VERSION 5.8 ;
BUSBITCHARS "[]" ;
DIVIDERCHAR "/" ;
UNITS
    DATABASE MICRONS 1000 ;
END UNITS

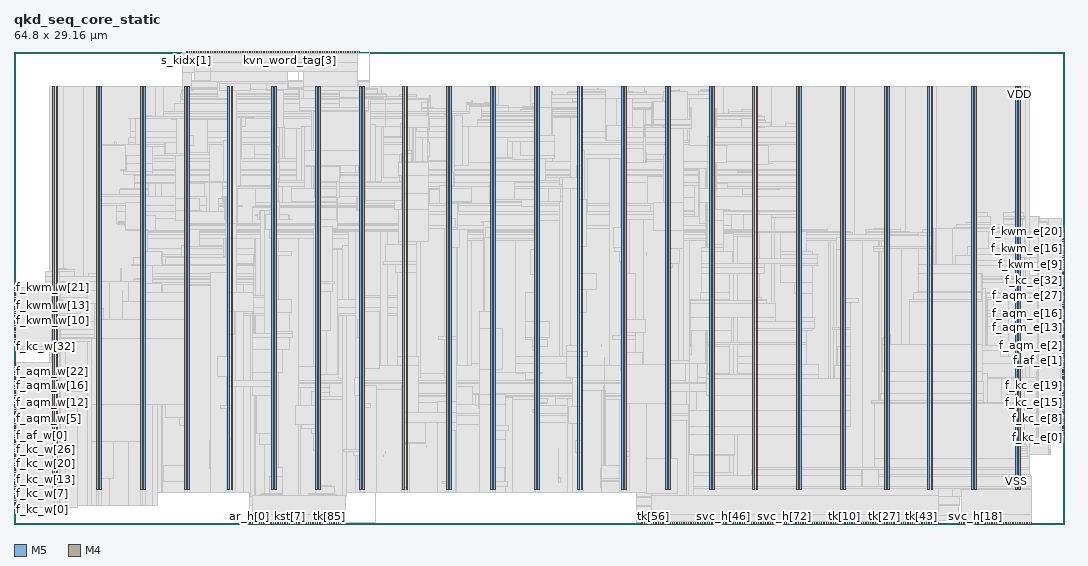
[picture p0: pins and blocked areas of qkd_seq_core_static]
MACRO qkd_seq_core_static
  FOREIGN qkd_seq_core_static 0 0 ;
  CLASS BLOCK ;
  SIZE 64.8 BY 29.16 ;
  PIN ar_h[0]
    DIRECTION INPUT ;
    USE SIGNAL ;
    PORT
      LAYER M5 ;
        RECT  14.544 0 14.568 0.084 ;
    END
  END ar_h[0]
  PIN ar_h[1]
    DIRECTION INPUT ;
    USE SIGNAL ;
    PORT
      LAYER M5 ;
        RECT  14.688 0 14.712 0.084 ;
    END
  END ar_h[1]
  PIN ar_h[2]
    DIRECTION INPUT ;
    USE SIGNAL ;
    PORT
      LAYER M5 ;
        RECT  14.832 0 14.856 0.084 ;
    END
  END ar_h[2]
  PIN ar_h[3]
    DIRECTION INPUT ;
    USE SIGNAL ;
    PORT
      LAYER M5 ;
        RECT  14.976 0 15 0.084 ;
    END
  END ar_h[3]
  PIN ar_h[4]
    DIRECTION INPUT ;
    USE SIGNAL ;
    PORT
      LAYER M5 ;
        RECT  15.12 0 15.144 0.084 ;
    END
  END ar_h[4]
  PIN ar_h[5]
    DIRECTION INPUT ;
    USE SIGNAL ;
    PORT
      LAYER M5 ;
        RECT  15.264 0 15.288 0.084 ;
    END
  END ar_h[5]
  PIN ar_h[6]
    DIRECTION INPUT ;
    USE SIGNAL ;
    PORT
      LAYER M5 ;
        RECT  15.408 0 15.432 0.084 ;
    END
  END ar_h[6]
  PIN ar_h[7]
    DIRECTION INPUT ;
    USE SIGNAL ;
    PORT
      LAYER M5 ;
        RECT  15.552 0 15.576 0.084 ;
    END
  END ar_h[7]
  PIN att_rx_beat[0]
    DIRECTION INPUT ;
    USE SIGNAL ;
    PORT
      LAYER M5 ;
        RECT  12.24 29.076 12.264 29.16 ;
    END
  END att_rx_beat[0]
  PIN att_rx_beat[1]
    DIRECTION INPUT ;
    USE SIGNAL ;
    PORT
      LAYER M5 ;
        RECT  12.384 29.076 12.408 29.16 ;
    END
  END att_rx_beat[1]
  PIN att_rx_beat[2]
    DIRECTION INPUT ;
    USE SIGNAL ;
    PORT
      LAYER M5 ;
        RECT  12.528 29.076 12.552 29.16 ;
    END
  END att_rx_beat[2]
  PIN att_rx_beat[3]
    DIRECTION INPUT ;
    USE SIGNAL ;
    PORT
      LAYER M5 ;
        RECT  12.672 29.076 12.696 29.16 ;
    END
  END att_rx_beat[3]
  PIN att_rx_beat[4]
    DIRECTION INPUT ;
    USE SIGNAL ;
    PORT
      LAYER M5 ;
        RECT  12.816 29.076 12.84 29.16 ;
    END
  END att_rx_beat[4]
  PIN att_rx_kind[0]
    DIRECTION INPUT ;
    USE SIGNAL ;
    PORT
      LAYER M5 ;
        RECT  12.96 29.076 12.984 29.16 ;
    END
  END att_rx_kind[0]
  PIN att_rx_kind[1]
    DIRECTION INPUT ;
    USE SIGNAL ;
    PORT
      LAYER M5 ;
        RECT  13.104 29.076 13.128 29.16 ;
    END
  END att_rx_kind[1]
  PIN att_rx_kind[2]
    DIRECTION INPUT ;
    USE SIGNAL ;
    PORT
      LAYER M5 ;
        RECT  13.248 29.076 13.272 29.16 ;
    END
  END att_rx_kind[2]
  PIN att_rx_kind[3]
    DIRECTION INPUT ;
    USE SIGNAL ;
    PORT
      LAYER M5 ;
        RECT  13.392 29.076 13.416 29.16 ;
    END
  END att_rx_kind[3]
  PIN att_rx_v
    DIRECTION INPUT ;
    USE SIGNAL ;
    PORT
      LAYER M5 ;
        RECT  13.536 29.076 13.56 29.16 ;
    END
  END att_rx_v
  PIN ck
    DIRECTION INPUT ;
    USE SIGNAL ;
    PORT
      LAYER M5 ;
        RECT  13.68 29.076 13.704 29.16 ;
    END
  END ck
  PIN cmd_d[0]
    DIRECTION INPUT ;
    USE SIGNAL ;
    PORT
      LAYER M5 ;
        RECT  13.824 29.076 13.848 29.16 ;
    END
  END cmd_d[0]
  PIN cmd_d[10]
    DIRECTION INPUT ;
    USE SIGNAL ;
    PORT
      LAYER M5 ;
        RECT  15.264 29.076 15.288 29.16 ;
    END
  END cmd_d[10]
  PIN cmd_d[11]
    DIRECTION INPUT ;
    USE SIGNAL ;
    PORT
      LAYER M5 ;
        RECT  15.408 29.076 15.432 29.16 ;
    END
  END cmd_d[11]
  PIN cmd_d[12]
    DIRECTION INPUT ;
    USE SIGNAL ;
    PORT
      LAYER M5 ;
        RECT  15.552 29.076 15.576 29.16 ;
    END
  END cmd_d[12]
  PIN cmd_d[13]
    DIRECTION INPUT ;
    USE SIGNAL ;
    PORT
      LAYER M5 ;
        RECT  15.696 29.076 15.72 29.16 ;
    END
  END cmd_d[13]
  PIN cmd_d[14]
    DIRECTION INPUT ;
    USE SIGNAL ;
    PORT
      LAYER M5 ;
        RECT  15.84 29.076 15.864 29.16 ;
    END
  END cmd_d[14]
  PIN cmd_d[15]
    DIRECTION INPUT ;
    USE SIGNAL ;
    PORT
      LAYER M5 ;
        RECT  15.984 29.076 16.008 29.16 ;
    END
  END cmd_d[15]
  PIN cmd_d[16]
    DIRECTION INPUT ;
    USE SIGNAL ;
    PORT
      LAYER M5 ;
        RECT  16.128 29.076 16.152 29.16 ;
    END
  END cmd_d[16]
  PIN cmd_d[17]
    DIRECTION INPUT ;
    USE SIGNAL ;
    PORT
      LAYER M5 ;
        RECT  16.272 29.076 16.296 29.16 ;
    END
  END cmd_d[17]
  PIN cmd_d[18]
    DIRECTION INPUT ;
    USE SIGNAL ;
    PORT
      LAYER M5 ;
        RECT  16.416 29.076 16.44 29.16 ;
    END
  END cmd_d[18]
  PIN cmd_d[1]
    DIRECTION INPUT ;
    USE SIGNAL ;
    PORT
      LAYER M5 ;
        RECT  13.968 29.076 13.992 29.16 ;
    END
  END cmd_d[1]
  PIN cmd_d[2]
    DIRECTION INPUT ;
    USE SIGNAL ;
    PORT
      LAYER M5 ;
        RECT  14.112 29.076 14.136 29.16 ;
    END
  END cmd_d[2]
  PIN cmd_d[3]
    DIRECTION INPUT ;
    USE SIGNAL ;
    PORT
      LAYER M5 ;
        RECT  14.256 29.076 14.28 29.16 ;
    END
  END cmd_d[3]
  PIN cmd_d[4]
    DIRECTION INPUT ;
    USE SIGNAL ;
    PORT
      LAYER M5 ;
        RECT  14.4 29.076 14.424 29.16 ;
    END
  END cmd_d[4]
  PIN cmd_d[5]
    DIRECTION INPUT ;
    USE SIGNAL ;
    PORT
      LAYER M5 ;
        RECT  14.544 29.076 14.568 29.16 ;
    END
  END cmd_d[5]
  PIN cmd_d[6]
    DIRECTION INPUT ;
    USE SIGNAL ;
    PORT
      LAYER M5 ;
        RECT  14.688 29.076 14.712 29.16 ;
    END
  END cmd_d[6]
  PIN cmd_d[7]
    DIRECTION INPUT ;
    USE SIGNAL ;
    PORT
      LAYER M5 ;
        RECT  14.832 29.076 14.856 29.16 ;
    END
  END cmd_d[7]
  PIN cmd_d[8]
    DIRECTION INPUT ;
    USE SIGNAL ;
    PORT
      LAYER M5 ;
        RECT  14.976 29.076 15 29.16 ;
    END
  END cmd_d[8]
  PIN cmd_d[9]
    DIRECTION INPUT ;
    USE SIGNAL ;
    PORT
      LAYER M5 ;
        RECT  15.12 29.076 15.144 29.16 ;
    END
  END cmd_d[9]
  PIN f_af_e[0]
    DIRECTION INPUT ;
    USE SIGNAL ;
    PORT
      LAYER M4 ;
        RECT  64.716 9.936 64.8 9.96 ;
    END
  END f_af_e[0]
  PIN f_af_e[1]
    DIRECTION INPUT ;
    USE SIGNAL ;
    PORT
      LAYER M4 ;
        RECT  64.716 10.08 64.8 10.104 ;
    END
  END f_af_e[1]
  PIN f_af_w[0]
    DIRECTION INPUT ;
    USE SIGNAL ;
    PORT
      LAYER M4 ;
        RECT  0 5.472 0.084 5.496 ;
    END
  END f_af_w[0]
  PIN f_af_w[1]
    DIRECTION INPUT ;
    USE SIGNAL ;
    PORT
      LAYER M4 ;
        RECT  0 5.616 0.084 5.64 ;
    END
  END f_af_w[1]
  PIN f_aqm_e[0]
    DIRECTION OUTPUT ;
    USE SIGNAL ;
    PORT
      LAYER M4 ;
        RECT  64.716 10.224 64.8 10.248 ;
    END
  END f_aqm_e[0]
  PIN f_aqm_e[10]
    DIRECTION OUTPUT ;
    USE SIGNAL ;
    PORT
      LAYER M4 ;
        RECT  64.716 11.664 64.8 11.688 ;
    END
  END f_aqm_e[10]
  PIN f_aqm_e[11]
    DIRECTION OUTPUT ;
    USE SIGNAL ;
    PORT
      LAYER M4 ;
        RECT  64.716 11.808 64.8 11.832 ;
    END
  END f_aqm_e[11]
  PIN f_aqm_e[12]
    DIRECTION OUTPUT ;
    USE SIGNAL ;
    PORT
      LAYER M4 ;
        RECT  64.716 11.952 64.8 11.976 ;
    END
  END f_aqm_e[12]
  PIN f_aqm_e[13]
    DIRECTION OUTPUT ;
    USE SIGNAL ;
    PORT
      LAYER M4 ;
        RECT  64.716 12.096 64.8 12.12 ;
    END
  END f_aqm_e[13]
  PIN f_aqm_e[14]
    DIRECTION OUTPUT ;
    USE SIGNAL ;
    PORT
      LAYER M4 ;
        RECT  64.716 12.24 64.8 12.264 ;
    END
  END f_aqm_e[14]
  PIN f_aqm_e[15]
    DIRECTION OUTPUT ;
    USE SIGNAL ;
    PORT
      LAYER M4 ;
        RECT  64.716 12.384 64.8 12.408 ;
    END
  END f_aqm_e[15]
  PIN f_aqm_e[16]
    DIRECTION OUTPUT ;
    USE SIGNAL ;
    PORT
      LAYER M4 ;
        RECT  64.716 12.528 64.8 12.552 ;
    END
  END f_aqm_e[16]
  PIN f_aqm_e[17]
    DIRECTION OUTPUT ;
    USE SIGNAL ;
    PORT
      LAYER M4 ;
        RECT  64.716 12.672 64.8 12.696 ;
    END
  END f_aqm_e[17]
  PIN f_aqm_e[18]
    DIRECTION OUTPUT ;
    USE SIGNAL ;
    PORT
      LAYER M4 ;
        RECT  64.716 12.816 64.8 12.84 ;
    END
  END f_aqm_e[18]
  PIN f_aqm_e[19]
    DIRECTION OUTPUT ;
    USE SIGNAL ;
    PORT
      LAYER M4 ;
        RECT  64.716 12.96 64.8 12.984 ;
    END
  END f_aqm_e[19]
  PIN f_aqm_e[1]
    DIRECTION OUTPUT ;
    USE SIGNAL ;
    PORT
      LAYER M4 ;
        RECT  64.716 10.368 64.8 10.392 ;
    END
  END f_aqm_e[1]
  PIN f_aqm_e[20]
    DIRECTION OUTPUT ;
    USE SIGNAL ;
    PORT
      LAYER M4 ;
        RECT  64.716 13.104 64.8 13.128 ;
    END
  END f_aqm_e[20]
  PIN f_aqm_e[21]
    DIRECTION OUTPUT ;
    USE SIGNAL ;
    PORT
      LAYER M4 ;
        RECT  64.716 13.248 64.8 13.272 ;
    END
  END f_aqm_e[21]
  PIN f_aqm_e[22]
    DIRECTION OUTPUT ;
    USE SIGNAL ;
    PORT
      LAYER M4 ;
        RECT  64.716 13.392 64.8 13.416 ;
    END
  END f_aqm_e[22]
  PIN f_aqm_e[23]
    DIRECTION OUTPUT ;
    USE SIGNAL ;
    PORT
      LAYER M4 ;
        RECT  64.716 13.536 64.8 13.56 ;
    END
  END f_aqm_e[23]
  PIN f_aqm_e[24]
    DIRECTION OUTPUT ;
    USE SIGNAL ;
    PORT
      LAYER M4 ;
        RECT  64.716 13.68 64.8 13.704 ;
    END
  END f_aqm_e[24]
  PIN f_aqm_e[25]
    DIRECTION OUTPUT ;
    USE SIGNAL ;
    PORT
      LAYER M4 ;
        RECT  64.716 13.824 64.8 13.848 ;
    END
  END f_aqm_e[25]
  PIN f_aqm_e[26]
    DIRECTION OUTPUT ;
    USE SIGNAL ;
    PORT
      LAYER M4 ;
        RECT  64.716 13.968 64.8 13.992 ;
    END
  END f_aqm_e[26]
  PIN f_aqm_e[27]
    DIRECTION OUTPUT ;
    USE SIGNAL ;
    PORT
      LAYER M4 ;
        RECT  64.716 14.112 64.8 14.136 ;
    END
  END f_aqm_e[27]
  PIN f_aqm_e[2]
    DIRECTION OUTPUT ;
    USE SIGNAL ;
    PORT
      LAYER M4 ;
        RECT  64.716 10.512 64.8 10.536 ;
    END
  END f_aqm_e[2]
  PIN f_aqm_e[3]
    DIRECTION OUTPUT ;
    USE SIGNAL ;
    PORT
      LAYER M4 ;
        RECT  64.716 10.656 64.8 10.68 ;
    END
  END f_aqm_e[3]
  PIN f_aqm_e[4]
    DIRECTION OUTPUT ;
    USE SIGNAL ;
    PORT
      LAYER M4 ;
        RECT  64.716 10.8 64.8 10.824 ;
    END
  END f_aqm_e[4]
  PIN f_aqm_e[5]
    DIRECTION OUTPUT ;
    USE SIGNAL ;
    PORT
      LAYER M4 ;
        RECT  64.716 10.944 64.8 10.968 ;
    END
  END f_aqm_e[5]
  PIN f_aqm_e[6]
    DIRECTION OUTPUT ;
    USE SIGNAL ;
    PORT
      LAYER M4 ;
        RECT  64.716 11.088 64.8 11.112 ;
    END
  END f_aqm_e[6]
  PIN f_aqm_e[7]
    DIRECTION OUTPUT ;
    USE SIGNAL ;
    PORT
      LAYER M4 ;
        RECT  64.716 11.232 64.8 11.256 ;
    END
  END f_aqm_e[7]
  PIN f_aqm_e[8]
    DIRECTION OUTPUT ;
    USE SIGNAL ;
    PORT
      LAYER M4 ;
        RECT  64.716 11.376 64.8 11.4 ;
    END
  END f_aqm_e[8]
  PIN f_aqm_e[9]
    DIRECTION OUTPUT ;
    USE SIGNAL ;
    PORT
      LAYER M4 ;
        RECT  64.716 11.52 64.8 11.544 ;
    END
  END f_aqm_e[9]
  PIN f_aqm_w[0]
    DIRECTION OUTPUT ;
    USE SIGNAL ;
    PORT
      LAYER M4 ;
        RECT  0 5.76 0.084 5.784 ;
    END
  END f_aqm_w[0]
  PIN f_aqm_w[10]
    DIRECTION OUTPUT ;
    USE SIGNAL ;
    PORT
      LAYER M4 ;
        RECT  0 7.2 0.084 7.224 ;
    END
  END f_aqm_w[10]
  PIN f_aqm_w[11]
    DIRECTION OUTPUT ;
    USE SIGNAL ;
    PORT
      LAYER M4 ;
        RECT  0 7.344 0.084 7.368 ;
    END
  END f_aqm_w[11]
  PIN f_aqm_w[12]
    DIRECTION OUTPUT ;
    USE SIGNAL ;
    PORT
      LAYER M4 ;
        RECT  0 7.488 0.084 7.512 ;
    END
  END f_aqm_w[12]
  PIN f_aqm_w[13]
    DIRECTION OUTPUT ;
    USE SIGNAL ;
    PORT
      LAYER M4 ;
        RECT  0 7.632 0.084 7.656 ;
    END
  END f_aqm_w[13]
  PIN f_aqm_w[14]
    DIRECTION OUTPUT ;
    USE SIGNAL ;
    PORT
      LAYER M4 ;
        RECT  0 7.776 0.084 7.8 ;
    END
  END f_aqm_w[14]
  PIN f_aqm_w[15]
    DIRECTION OUTPUT ;
    USE SIGNAL ;
    PORT
      LAYER M4 ;
        RECT  0 7.92 0.084 7.944 ;
    END
  END f_aqm_w[15]
  PIN f_aqm_w[16]
    DIRECTION OUTPUT ;
    USE SIGNAL ;
    PORT
      LAYER M4 ;
        RECT  0 8.064 0.084 8.088 ;
    END
  END f_aqm_w[16]
  PIN f_aqm_w[17]
    DIRECTION OUTPUT ;
    USE SIGNAL ;
    PORT
      LAYER M4 ;
        RECT  0 8.208 0.084 8.232 ;
    END
  END f_aqm_w[17]
  PIN f_aqm_w[18]
    DIRECTION OUTPUT ;
    USE SIGNAL ;
    PORT
      LAYER M4 ;
        RECT  0 8.352 0.084 8.376 ;
    END
  END f_aqm_w[18]
  PIN f_aqm_w[19]
    DIRECTION OUTPUT ;
    USE SIGNAL ;
    PORT
      LAYER M4 ;
        RECT  0 8.496 0.084 8.52 ;
    END
  END f_aqm_w[19]
  PIN f_aqm_w[1]
    DIRECTION OUTPUT ;
    USE SIGNAL ;
    PORT
      LAYER M4 ;
        RECT  0 5.904 0.084 5.928 ;
    END
  END f_aqm_w[1]
  PIN f_aqm_w[20]
    DIRECTION OUTPUT ;
    USE SIGNAL ;
    PORT
      LAYER M4 ;
        RECT  0 8.64 0.084 8.664 ;
    END
  END f_aqm_w[20]
  PIN f_aqm_w[21]
    DIRECTION OUTPUT ;
    USE SIGNAL ;
    PORT
      LAYER M4 ;
        RECT  0 8.784 0.084 8.808 ;
    END
  END f_aqm_w[21]
  PIN f_aqm_w[22]
    DIRECTION OUTPUT ;
    USE SIGNAL ;
    PORT
      LAYER M4 ;
        RECT  0 8.928 0.084 8.952 ;
    END
  END f_aqm_w[22]
  PIN f_aqm_w[23]
    DIRECTION OUTPUT ;
    USE SIGNAL ;
    PORT
      LAYER M4 ;
        RECT  0 9.072 0.084 9.096 ;
    END
  END f_aqm_w[23]
  PIN f_aqm_w[24]
    DIRECTION OUTPUT ;
    USE SIGNAL ;
    PORT
      LAYER M4 ;
        RECT  0 9.216 0.084 9.24 ;
    END
  END f_aqm_w[24]
  PIN f_aqm_w[25]
    DIRECTION OUTPUT ;
    USE SIGNAL ;
    PORT
      LAYER M4 ;
        RECT  0 9.36 0.084 9.384 ;
    END
  END f_aqm_w[25]
  PIN f_aqm_w[26]
    DIRECTION OUTPUT ;
    USE SIGNAL ;
    PORT
      LAYER M4 ;
        RECT  0 9.504 0.084 9.528 ;
    END
  END f_aqm_w[26]
  PIN f_aqm_w[27]
    DIRECTION OUTPUT ;
    USE SIGNAL ;
    PORT
      LAYER M4 ;
        RECT  0 9.648 0.084 9.672 ;
    END
  END f_aqm_w[27]
  PIN f_aqm_w[2]
    DIRECTION OUTPUT ;
    USE SIGNAL ;
    PORT
      LAYER M4 ;
        RECT  0 6.048 0.084 6.072 ;
    END
  END f_aqm_w[2]
  PIN f_aqm_w[3]
    DIRECTION OUTPUT ;
    USE SIGNAL ;
    PORT
      LAYER M4 ;
        RECT  0 6.192 0.084 6.216 ;
    END
  END f_aqm_w[3]
  PIN f_aqm_w[4]
    DIRECTION OUTPUT ;
    USE SIGNAL ;
    PORT
      LAYER M4 ;
        RECT  0 6.336 0.084 6.36 ;
    END
  END f_aqm_w[4]
  PIN f_aqm_w[5]
    DIRECTION OUTPUT ;
    USE SIGNAL ;
    PORT
      LAYER M4 ;
        RECT  0 6.48 0.084 6.504 ;
    END
  END f_aqm_w[5]
  PIN f_aqm_w[6]
    DIRECTION OUTPUT ;
    USE SIGNAL ;
    PORT
      LAYER M4 ;
        RECT  0 6.624 0.084 6.648 ;
    END
  END f_aqm_w[6]
  PIN f_aqm_w[7]
    DIRECTION OUTPUT ;
    USE SIGNAL ;
    PORT
      LAYER M4 ;
        RECT  0 6.768 0.084 6.792 ;
    END
  END f_aqm_w[7]
  PIN f_aqm_w[8]
    DIRECTION OUTPUT ;
    USE SIGNAL ;
    PORT
      LAYER M4 ;
        RECT  0 6.912 0.084 6.936 ;
    END
  END f_aqm_w[8]
  PIN f_aqm_w[9]
    DIRECTION OUTPUT ;
    USE SIGNAL ;
    PORT
      LAYER M4 ;
        RECT  0 7.056 0.084 7.08 ;
    END
  END f_aqm_w[9]
  PIN f_cr_e[0]
    DIRECTION INPUT ;
    USE SIGNAL ;
    PORT
      LAYER M4 ;
        RECT  64.716 14.256 64.8 14.28 ;
    END
  END f_cr_e[0]
  PIN f_cr_e[1]
    DIRECTION INPUT ;
    USE SIGNAL ;
    PORT
      LAYER M4 ;
        RECT  64.716 14.4 64.8 14.424 ;
    END
  END f_cr_e[1]
  PIN f_cr_w[0]
    DIRECTION INPUT ;
    USE SIGNAL ;
    PORT
      LAYER M4 ;
        RECT  0 9.792 0.084 9.816 ;
    END
  END f_cr_w[0]
  PIN f_cr_w[1]
    DIRECTION INPUT ;
    USE SIGNAL ;
    PORT
      LAYER M4 ;
        RECT  0 9.936 0.084 9.96 ;
    END
  END f_cr_w[1]
  PIN f_kc_e[0]
    DIRECTION OUTPUT ;
    USE SIGNAL ;
    PORT
      LAYER M4 ;
        RECT  64.716 5.328 64.8 5.352 ;
    END
  END f_kc_e[0]
  PIN f_kc_e[10]
    DIRECTION OUTPUT ;
    USE SIGNAL ;
    PORT
      LAYER M4 ;
        RECT  64.716 6.768 64.8 6.792 ;
    END
  END f_kc_e[10]
  PIN f_kc_e[11]
    DIRECTION OUTPUT ;
    USE SIGNAL ;
    PORT
      LAYER M4 ;
        RECT  64.716 6.912 64.8 6.936 ;
    END
  END f_kc_e[11]
  PIN f_kc_e[12]
    DIRECTION OUTPUT ;
    USE SIGNAL ;
    PORT
      LAYER M4 ;
        RECT  64.716 7.056 64.8 7.08 ;
    END
  END f_kc_e[12]
  PIN f_kc_e[13]
    DIRECTION OUTPUT ;
    USE SIGNAL ;
    PORT
      LAYER M4 ;
        RECT  64.716 7.2 64.8 7.224 ;
    END
  END f_kc_e[13]
  PIN f_kc_e[14]
    DIRECTION OUTPUT ;
    USE SIGNAL ;
    PORT
      LAYER M4 ;
        RECT  64.716 7.344 64.8 7.368 ;
    END
  END f_kc_e[14]
  PIN f_kc_e[15]
    DIRECTION OUTPUT ;
    USE SIGNAL ;
    PORT
      LAYER M4 ;
        RECT  64.716 7.488 64.8 7.512 ;
    END
  END f_kc_e[15]
  PIN f_kc_e[16]
    DIRECTION OUTPUT ;
    USE SIGNAL ;
    PORT
      LAYER M4 ;
        RECT  64.716 7.632 64.8 7.656 ;
    END
  END f_kc_e[16]
  PIN f_kc_e[17]
    DIRECTION OUTPUT ;
    USE SIGNAL ;
    PORT
      LAYER M4 ;
        RECT  64.716 7.776 64.8 7.8 ;
    END
  END f_kc_e[17]
  PIN f_kc_e[18]
    DIRECTION OUTPUT ;
    USE SIGNAL ;
    PORT
      LAYER M4 ;
        RECT  64.716 7.92 64.8 7.944 ;
    END
  END f_kc_e[18]
  PIN f_kc_e[19]
    DIRECTION OUTPUT ;
    USE SIGNAL ;
    PORT
      LAYER M4 ;
        RECT  64.716 8.064 64.8 8.088 ;
    END
  END f_kc_e[19]
  PIN f_kc_e[1]
    DIRECTION OUTPUT ;
    USE SIGNAL ;
    PORT
      LAYER M4 ;
        RECT  64.716 5.472 64.8 5.496 ;
    END
  END f_kc_e[1]
  PIN f_kc_e[20]
    DIRECTION OUTPUT ;
    USE SIGNAL ;
    PORT
      LAYER M4 ;
        RECT  64.716 8.208 64.8 8.232 ;
    END
  END f_kc_e[20]
  PIN f_kc_e[21]
    DIRECTION OUTPUT ;
    USE SIGNAL ;
    PORT
      LAYER M4 ;
        RECT  64.716 8.352 64.8 8.376 ;
    END
  END f_kc_e[21]
  PIN f_kc_e[22]
    DIRECTION OUTPUT ;
    USE SIGNAL ;
    PORT
      LAYER M4 ;
        RECT  64.716 8.496 64.8 8.52 ;
    END
  END f_kc_e[22]
  PIN f_kc_e[23]
    DIRECTION OUTPUT ;
    USE SIGNAL ;
    PORT
      LAYER M4 ;
        RECT  64.716 8.64 64.8 8.664 ;
    END
  END f_kc_e[23]
  PIN f_kc_e[24]
    DIRECTION OUTPUT ;
    USE SIGNAL ;
    PORT
      LAYER M4 ;
        RECT  64.716 8.784 64.8 8.808 ;
    END
  END f_kc_e[24]
  PIN f_kc_e[25]
    DIRECTION OUTPUT ;
    USE SIGNAL ;
    PORT
      LAYER M4 ;
        RECT  64.716 8.928 64.8 8.952 ;
    END
  END f_kc_e[25]
  PIN f_kc_e[26]
    DIRECTION OUTPUT ;
    USE SIGNAL ;
    PORT
      LAYER M4 ;
        RECT  64.716 9.072 64.8 9.096 ;
    END
  END f_kc_e[26]
  PIN f_kc_e[27]
    DIRECTION OUTPUT ;
    USE SIGNAL ;
    PORT
      LAYER M4 ;
        RECT  64.716 9.216 64.8 9.24 ;
    END
  END f_kc_e[27]
  PIN f_kc_e[28]
    DIRECTION OUTPUT ;
    USE SIGNAL ;
    PORT
      LAYER M4 ;
        RECT  64.716 9.36 64.8 9.384 ;
    END
  END f_kc_e[28]
  PIN f_kc_e[29]
    DIRECTION OUTPUT ;
    USE SIGNAL ;
    PORT
      LAYER M4 ;
        RECT  64.716 9.504 64.8 9.528 ;
    END
  END f_kc_e[29]
  PIN f_kc_e[2]
    DIRECTION OUTPUT ;
    USE SIGNAL ;
    PORT
      LAYER M4 ;
        RECT  64.716 5.616 64.8 5.64 ;
    END
  END f_kc_e[2]
  PIN f_kc_e[30]
    DIRECTION OUTPUT ;
    USE SIGNAL ;
    PORT
      LAYER M4 ;
        RECT  64.716 9.648 64.8 9.672 ;
    END
  END f_kc_e[30]
  PIN f_kc_e[31]
    DIRECTION OUTPUT ;
    USE SIGNAL ;
    PORT
      LAYER M4 ;
        RECT  64.716 9.792 64.8 9.816 ;
    END
  END f_kc_e[31]
  PIN f_kc_e[32]
    DIRECTION OUTPUT ;
    USE SIGNAL ;
    PORT
      LAYER M4 ;
        RECT  64.716 14.544 64.8 14.568 ;
    END
  END f_kc_e[32]
  PIN f_kc_e[3]
    DIRECTION OUTPUT ;
    USE SIGNAL ;
    PORT
      LAYER M4 ;
        RECT  64.716 5.76 64.8 5.784 ;
    END
  END f_kc_e[3]
  PIN f_kc_e[4]
    DIRECTION OUTPUT ;
    USE SIGNAL ;
    PORT
      LAYER M4 ;
        RECT  64.716 5.904 64.8 5.928 ;
    END
  END f_kc_e[4]
  PIN f_kc_e[5]
    DIRECTION OUTPUT ;
    USE SIGNAL ;
    PORT
      LAYER M4 ;
        RECT  64.716 6.048 64.8 6.072 ;
    END
  END f_kc_e[5]
  PIN f_kc_e[6]
    DIRECTION OUTPUT ;
    USE SIGNAL ;
    PORT
      LAYER M4 ;
        RECT  64.716 6.192 64.8 6.216 ;
    END
  END f_kc_e[6]
  PIN f_kc_e[7]
    DIRECTION OUTPUT ;
    USE SIGNAL ;
    PORT
      LAYER M4 ;
        RECT  64.716 6.336 64.8 6.36 ;
    END
  END f_kc_e[7]
  PIN f_kc_e[8]
    DIRECTION OUTPUT ;
    USE SIGNAL ;
    PORT
      LAYER M4 ;
        RECT  64.716 6.48 64.8 6.504 ;
    END
  END f_kc_e[8]
  PIN f_kc_e[9]
    DIRECTION OUTPUT ;
    USE SIGNAL ;
    PORT
      LAYER M4 ;
        RECT  64.716 6.624 64.8 6.648 ;
    END
  END f_kc_e[9]
  PIN f_kc_w[0]
    DIRECTION OUTPUT ;
    USE SIGNAL ;
    PORT
      LAYER M4 ;
        RECT  0 0.864 0.084 0.888 ;
    END
  END f_kc_w[0]
  PIN f_kc_w[10]
    DIRECTION OUTPUT ;
    USE SIGNAL ;
    PORT
      LAYER M4 ;
        RECT  0 2.304 0.084 2.328 ;
    END
  END f_kc_w[10]
  PIN f_kc_w[11]
    DIRECTION OUTPUT ;
    USE SIGNAL ;
    PORT
      LAYER M4 ;
        RECT  0 2.448 0.084 2.472 ;
    END
  END f_kc_w[11]
  PIN f_kc_w[12]
    DIRECTION OUTPUT ;
    USE SIGNAL ;
    PORT
      LAYER M4 ;
        RECT  0 2.592 0.084 2.616 ;
    END
  END f_kc_w[12]
  PIN f_kc_w[13]
    DIRECTION OUTPUT ;
    USE SIGNAL ;
    PORT
      LAYER M4 ;
        RECT  0 2.736 0.084 2.76 ;
    END
  END f_kc_w[13]
  PIN f_kc_w[14]
    DIRECTION OUTPUT ;
    USE SIGNAL ;
    PORT
      LAYER M4 ;
        RECT  0 2.88 0.084 2.904 ;
    END
  END f_kc_w[14]
  PIN f_kc_w[15]
    DIRECTION OUTPUT ;
    USE SIGNAL ;
    PORT
      LAYER M4 ;
        RECT  0 3.024 0.084 3.048 ;
    END
  END f_kc_w[15]
  PIN f_kc_w[16]
    DIRECTION OUTPUT ;
    USE SIGNAL ;
    PORT
      LAYER M4 ;
        RECT  0 3.168 0.084 3.192 ;
    END
  END f_kc_w[16]
  PIN f_kc_w[17]
    DIRECTION OUTPUT ;
    USE SIGNAL ;
    PORT
      LAYER M4 ;
        RECT  0 3.312 0.084 3.336 ;
    END
  END f_kc_w[17]
  PIN f_kc_w[18]
    DIRECTION OUTPUT ;
    USE SIGNAL ;
    PORT
      LAYER M4 ;
        RECT  0 3.456 0.084 3.48 ;
    END
  END f_kc_w[18]
  PIN f_kc_w[19]
    DIRECTION OUTPUT ;
    USE SIGNAL ;
    PORT
      LAYER M4 ;
        RECT  0 3.6 0.084 3.624 ;
    END
  END f_kc_w[19]
  PIN f_kc_w[1]
    DIRECTION OUTPUT ;
    USE SIGNAL ;
    PORT
      LAYER M4 ;
        RECT  0 1.008 0.084 1.032 ;
    END
  END f_kc_w[1]
  PIN f_kc_w[20]
    DIRECTION OUTPUT ;
    USE SIGNAL ;
    PORT
      LAYER M4 ;
        RECT  0 3.744 0.084 3.768 ;
    END
  END f_kc_w[20]
  PIN f_kc_w[21]
    DIRECTION OUTPUT ;
    USE SIGNAL ;
    PORT
      LAYER M4 ;
        RECT  0 3.888 0.084 3.912 ;
    END
  END f_kc_w[21]
  PIN f_kc_w[22]
    DIRECTION OUTPUT ;
    USE SIGNAL ;
    PORT
      LAYER M4 ;
        RECT  0 4.032 0.084 4.056 ;
    END
  END f_kc_w[22]
  PIN f_kc_w[23]
    DIRECTION OUTPUT ;
    USE SIGNAL ;
    PORT
      LAYER M4 ;
        RECT  0 4.176 0.084 4.2 ;
    END
  END f_kc_w[23]
  PIN f_kc_w[24]
    DIRECTION OUTPUT ;
    USE SIGNAL ;
    PORT
      LAYER M4 ;
        RECT  0 4.32 0.084 4.344 ;
    END
  END f_kc_w[24]
  PIN f_kc_w[25]
    DIRECTION OUTPUT ;
    USE SIGNAL ;
    PORT
      LAYER M4 ;
        RECT  0 4.464 0.084 4.488 ;
    END
  END f_kc_w[25]
  PIN f_kc_w[26]
    DIRECTION OUTPUT ;
    USE SIGNAL ;
    PORT
      LAYER M4 ;
        RECT  0 4.608 0.084 4.632 ;
    END
  END f_kc_w[26]
  PIN f_kc_w[27]
    DIRECTION OUTPUT ;
    USE SIGNAL ;
    PORT
      LAYER M4 ;
        RECT  0 4.752 0.084 4.776 ;
    END
  END f_kc_w[27]
  PIN f_kc_w[28]
    DIRECTION OUTPUT ;
    USE SIGNAL ;
    PORT
      LAYER M4 ;
        RECT  0 4.896 0.084 4.92 ;
    END
  END f_kc_w[28]
  PIN f_kc_w[29]
    DIRECTION OUTPUT ;
    USE SIGNAL ;
    PORT
      LAYER M4 ;
        RECT  0 5.04 0.084 5.064 ;
    END
  END f_kc_w[29]
  PIN f_kc_w[2]
    DIRECTION OUTPUT ;
    USE SIGNAL ;
    PORT
      LAYER M4 ;
        RECT  0 1.152 0.084 1.176 ;
    END
  END f_kc_w[2]
  PIN f_kc_w[30]
    DIRECTION OUTPUT ;
    USE SIGNAL ;
    PORT
      LAYER M4 ;
        RECT  0 5.184 0.084 5.208 ;
    END
  END f_kc_w[30]
  PIN f_kc_w[31]
    DIRECTION OUTPUT ;
    USE SIGNAL ;
    PORT
      LAYER M4 ;
        RECT  0 5.328 0.084 5.352 ;
    END
  END f_kc_w[31]
  PIN f_kc_w[32]
    DIRECTION OUTPUT ;
    USE SIGNAL ;
    PORT
      LAYER M4 ;
        RECT  0 10.944 0.084 10.968 ;
    END
  END f_kc_w[32]
  PIN f_kc_w[3]
    DIRECTION OUTPUT ;
    USE SIGNAL ;
    PORT
      LAYER M4 ;
        RECT  0 1.296 0.084 1.32 ;
    END
  END f_kc_w[3]
  PIN f_kc_w[4]
    DIRECTION OUTPUT ;
    USE SIGNAL ;
    PORT
      LAYER M4 ;
        RECT  0 1.44 0.084 1.464 ;
    END
  END f_kc_w[4]
  PIN f_kc_w[5]
    DIRECTION OUTPUT ;
    USE SIGNAL ;
    PORT
      LAYER M4 ;
        RECT  0 1.584 0.084 1.608 ;
    END
  END f_kc_w[5]
  PIN f_kc_w[6]
    DIRECTION OUTPUT ;
    USE SIGNAL ;
    PORT
      LAYER M4 ;
        RECT  0 1.728 0.084 1.752 ;
    END
  END f_kc_w[6]
  PIN f_kc_w[7]
    DIRECTION OUTPUT ;
    USE SIGNAL ;
    PORT
      LAYER M4 ;
        RECT  0 1.872 0.084 1.896 ;
    END
  END f_kc_w[7]
  PIN f_kc_w[8]
    DIRECTION OUTPUT ;
    USE SIGNAL ;
    PORT
      LAYER M4 ;
        RECT  0 2.016 0.084 2.04 ;
    END
  END f_kc_w[8]
  PIN f_kc_w[9]
    DIRECTION OUTPUT ;
    USE SIGNAL ;
    PORT
      LAYER M4 ;
        RECT  0 2.16 0.084 2.184 ;
    END
  END f_kc_w[9]
  PIN f_kwm_e[0]
    DIRECTION OUTPUT ;
    USE SIGNAL ;
    PORT
      LAYER M4 ;
        RECT  64.716 14.688 64.8 14.712 ;
    END
  END f_kwm_e[0]
  PIN f_kwm_e[10]
    DIRECTION OUTPUT ;
    USE SIGNAL ;
    PORT
      LAYER M4 ;
        RECT  64.716 16.128 64.8 16.152 ;
    END
  END f_kwm_e[10]
  PIN f_kwm_e[11]
    DIRECTION OUTPUT ;
    USE SIGNAL ;
    PORT
      LAYER M4 ;
        RECT  64.716 16.272 64.8 16.296 ;
    END
  END f_kwm_e[11]
  PIN f_kwm_e[12]
    DIRECTION OUTPUT ;
    USE SIGNAL ;
    PORT
      LAYER M4 ;
        RECT  64.716 16.416 64.8 16.44 ;
    END
  END f_kwm_e[12]
  PIN f_kwm_e[13]
    DIRECTION OUTPUT ;
    USE SIGNAL ;
    PORT
      LAYER M4 ;
        RECT  64.716 16.56 64.8 16.584 ;
    END
  END f_kwm_e[13]
  PIN f_kwm_e[14]
    DIRECTION OUTPUT ;
    USE SIGNAL ;
    PORT
      LAYER M4 ;
        RECT  64.716 16.704 64.8 16.728 ;
    END
  END f_kwm_e[14]
  PIN f_kwm_e[15]
    DIRECTION OUTPUT ;
    USE SIGNAL ;
    PORT
      LAYER M4 ;
        RECT  64.716 16.848 64.8 16.872 ;
    END
  END f_kwm_e[15]
  PIN f_kwm_e[16]
    DIRECTION OUTPUT ;
    USE SIGNAL ;
    PORT
      LAYER M4 ;
        RECT  64.716 16.992 64.8 17.016 ;
    END
  END f_kwm_e[16]
  PIN f_kwm_e[17]
    DIRECTION OUTPUT ;
    USE SIGNAL ;
    PORT
      LAYER M4 ;
        RECT  64.716 17.136 64.8 17.16 ;
    END
  END f_kwm_e[17]
  PIN f_kwm_e[18]
    DIRECTION OUTPUT ;
    USE SIGNAL ;
    PORT
      LAYER M4 ;
        RECT  64.716 17.28 64.8 17.304 ;
    END
  END f_kwm_e[18]
  PIN f_kwm_e[19]
    DIRECTION OUTPUT ;
    USE SIGNAL ;
    PORT
      LAYER M4 ;
        RECT  64.716 17.424 64.8 17.448 ;
    END
  END f_kwm_e[19]
  PIN f_kwm_e[1]
    DIRECTION OUTPUT ;
    USE SIGNAL ;
    PORT
      LAYER M4 ;
        RECT  64.716 14.832 64.8 14.856 ;
    END
  END f_kwm_e[1]
  PIN f_kwm_e[20]
    DIRECTION OUTPUT ;
    USE SIGNAL ;
    PORT
      LAYER M4 ;
        RECT  64.716 17.568 64.8 17.592 ;
    END
  END f_kwm_e[20]
  PIN f_kwm_e[21]
    DIRECTION OUTPUT ;
    USE SIGNAL ;
    PORT
      LAYER M4 ;
        RECT  64.716 17.712 64.8 17.736 ;
    END
  END f_kwm_e[21]
  PIN f_kwm_e[22]
    DIRECTION OUTPUT ;
    USE SIGNAL ;
    PORT
      LAYER M4 ;
        RECT  64.716 17.856 64.8 17.88 ;
    END
  END f_kwm_e[22]
  PIN f_kwm_e[2]
    DIRECTION OUTPUT ;
    USE SIGNAL ;
    PORT
      LAYER M4 ;
        RECT  64.716 14.976 64.8 15 ;
    END
  END f_kwm_e[2]
  PIN f_kwm_e[3]
    DIRECTION OUTPUT ;
    USE SIGNAL ;
    PORT
      LAYER M4 ;
        RECT  64.716 15.12 64.8 15.144 ;
    END
  END f_kwm_e[3]
  PIN f_kwm_e[4]
    DIRECTION OUTPUT ;
    USE SIGNAL ;
    PORT
      LAYER M4 ;
        RECT  64.716 15.264 64.8 15.288 ;
    END
  END f_kwm_e[4]
  PIN f_kwm_e[5]
    DIRECTION OUTPUT ;
    USE SIGNAL ;
    PORT
      LAYER M4 ;
        RECT  64.716 15.408 64.8 15.432 ;
    END
  END f_kwm_e[5]
  PIN f_kwm_e[6]
    DIRECTION OUTPUT ;
    USE SIGNAL ;
    PORT
      LAYER M4 ;
        RECT  64.716 15.552 64.8 15.576 ;
    END
  END f_kwm_e[6]
  PIN f_kwm_e[7]
    DIRECTION OUTPUT ;
    USE SIGNAL ;
    PORT
      LAYER M4 ;
        RECT  64.716 15.696 64.8 15.72 ;
    END
  END f_kwm_e[7]
  PIN f_kwm_e[8]
    DIRECTION OUTPUT ;
    USE SIGNAL ;
    PORT
      LAYER M4 ;
        RECT  64.716 15.84 64.8 15.864 ;
    END
  END f_kwm_e[8]
  PIN f_kwm_e[9]
    DIRECTION OUTPUT ;
    USE SIGNAL ;
    PORT
      LAYER M4 ;
        RECT  64.716 15.984 64.8 16.008 ;
    END
  END f_kwm_e[9]
  PIN f_kwm_w[0]
    DIRECTION OUTPUT ;
    USE SIGNAL ;
    PORT
      LAYER M4 ;
        RECT  0 11.088 0.084 11.112 ;
    END
  END f_kwm_w[0]
  PIN f_kwm_w[10]
    DIRECTION OUTPUT ;
    USE SIGNAL ;
    PORT
      LAYER M4 ;
        RECT  0 12.528 0.084 12.552 ;
    END
  END f_kwm_w[10]
  PIN f_kwm_w[11]
    DIRECTION OUTPUT ;
    USE SIGNAL ;
    PORT
      LAYER M4 ;
        RECT  0 12.672 0.084 12.696 ;
    END
  END f_kwm_w[11]
  PIN f_kwm_w[12]
    DIRECTION OUTPUT ;
    USE SIGNAL ;
    PORT
      LAYER M4 ;
        RECT  0 12.816 0.084 12.84 ;
    END
  END f_kwm_w[12]
  PIN f_kwm_w[13]
    DIRECTION OUTPUT ;
    USE SIGNAL ;
    PORT
      LAYER M4 ;
        RECT  0 12.96 0.084 12.984 ;
    END
  END f_kwm_w[13]
  PIN f_kwm_w[14]
    DIRECTION OUTPUT ;
    USE SIGNAL ;
    PORT
      LAYER M4 ;
        RECT  0 13.104 0.084 13.128 ;
    END
  END f_kwm_w[14]
  PIN f_kwm_w[15]
    DIRECTION OUTPUT ;
    USE SIGNAL ;
    PORT
      LAYER M4 ;
        RECT  0 13.248 0.084 13.272 ;
    END
  END f_kwm_w[15]
  PIN f_kwm_w[16]
    DIRECTION OUTPUT ;
    USE SIGNAL ;
    PORT
      LAYER M4 ;
        RECT  0 13.392 0.084 13.416 ;
    END
  END f_kwm_w[16]
  PIN f_kwm_w[17]
    DIRECTION OUTPUT ;
    USE SIGNAL ;
    PORT
      LAYER M4 ;
        RECT  0 13.536 0.084 13.56 ;
    END
  END f_kwm_w[17]
  PIN f_kwm_w[18]
    DIRECTION OUTPUT ;
    USE SIGNAL ;
    PORT
      LAYER M4 ;
        RECT  0 13.68 0.084 13.704 ;
    END
  END f_kwm_w[18]
  PIN f_kwm_w[19]
    DIRECTION OUTPUT ;
    USE SIGNAL ;
    PORT
      LAYER M4 ;
        RECT  0 13.824 0.084 13.848 ;
    END
  END f_kwm_w[19]
  PIN f_kwm_w[1]
    DIRECTION OUTPUT ;
    USE SIGNAL ;
    PORT
      LAYER M4 ;
        RECT  0 11.232 0.084 11.256 ;
    END
  END f_kwm_w[1]
  PIN f_kwm_w[20]
    DIRECTION OUTPUT ;
    USE SIGNAL ;
    PORT
      LAYER M4 ;
        RECT  0 13.968 0.084 13.992 ;
    END
  END f_kwm_w[20]
  PIN f_kwm_w[21]
    DIRECTION OUTPUT ;
    USE SIGNAL ;
    PORT
      LAYER M4 ;
        RECT  0 14.112 0.084 14.136 ;
    END
  END f_kwm_w[21]
  PIN f_kwm_w[22]
    DIRECTION OUTPUT ;
    USE SIGNAL ;
    PORT
      LAYER M4 ;
        RECT  0 14.256 0.084 14.28 ;
    END
  END f_kwm_w[22]
  PIN f_kwm_w[2]
    DIRECTION OUTPUT ;
    USE SIGNAL ;
    PORT
      LAYER M4 ;
        RECT  0 11.376 0.084 11.4 ;
    END
  END f_kwm_w[2]
  PIN f_kwm_w[3]
    DIRECTION OUTPUT ;
    USE SIGNAL ;
    PORT
      LAYER M4 ;
        RECT  0 11.52 0.084 11.544 ;
    END
  END f_kwm_w[3]
  PIN f_kwm_w[4]
    DIRECTION OUTPUT ;
    USE SIGNAL ;
    PORT
      LAYER M4 ;
        RECT  0 11.664 0.084 11.688 ;
    END
  END f_kwm_w[4]
  PIN f_kwm_w[5]
    DIRECTION OUTPUT ;
    USE SIGNAL ;
    PORT
      LAYER M4 ;
        RECT  0 11.808 0.084 11.832 ;
    END
  END f_kwm_w[5]
  PIN f_kwm_w[6]
    DIRECTION OUTPUT ;
    USE SIGNAL ;
    PORT
      LAYER M4 ;
        RECT  0 11.952 0.084 11.976 ;
    END
  END f_kwm_w[6]
  PIN f_kwm_w[7]
    DIRECTION OUTPUT ;
    USE SIGNAL ;
    PORT
      LAYER M4 ;
        RECT  0 12.096 0.084 12.12 ;
    END
  END f_kwm_w[7]
  PIN f_kwm_w[8]
    DIRECTION OUTPUT ;
    USE SIGNAL ;
    PORT
      LAYER M4 ;
        RECT  0 12.24 0.084 12.264 ;
    END
  END f_kwm_w[8]
  PIN f_kwm_w[9]
    DIRECTION OUTPUT ;
    USE SIGNAL ;
    PORT
      LAYER M4 ;
        RECT  0 12.384 0.084 12.408 ;
    END
  END f_kwm_w[9]
  PIN f_mf_e[0]
    DIRECTION INPUT ;
    USE SIGNAL ;
    PORT
      LAYER M4 ;
        RECT  64.716 18 64.8 18.024 ;
    END
  END f_mf_e[0]
  PIN f_mf_e[1]
    DIRECTION INPUT ;
    USE SIGNAL ;
    PORT
      LAYER M4 ;
        RECT  64.716 18.144 64.8 18.168 ;
    END
  END f_mf_e[1]
  PIN f_mf_w[0]
    DIRECTION INPUT ;
    USE SIGNAL ;
    PORT
      LAYER M4 ;
        RECT  0 14.4 0.084 14.424 ;
    END
  END f_mf_w[0]
  PIN f_mf_w[1]
    DIRECTION INPUT ;
    USE SIGNAL ;
    PORT
      LAYER M4 ;
        RECT  0 14.544 0.084 14.568 ;
    END
  END f_mf_w[1]
  PIN hf
    DIRECTION INPUT ;
    USE SIGNAL ;
    PORT
      LAYER M5 ;
        RECT  15.696 0 15.72 0.084 ;
    END
  END hf
  PIN hs
    DIRECTION OUTPUT ;
    USE SIGNAL ;
    PORT
      LAYER M5 ;
        RECT  15.84 0 15.864 0.084 ;
    END
  END hs
  PIN kst[0]
    DIRECTION OUTPUT ;
    USE SIGNAL ;
    PORT
      LAYER M5 ;
        RECT  15.984 0 16.008 0.084 ;
    END
  END kst[0]
  PIN kst[1]
    DIRECTION OUTPUT ;
    USE SIGNAL ;
    PORT
      LAYER M5 ;
        RECT  16.128 0 16.152 0.084 ;
    END
  END kst[1]
  PIN kst[2]
    DIRECTION OUTPUT ;
    USE SIGNAL ;
    PORT
      LAYER M5 ;
        RECT  16.272 0 16.296 0.084 ;
    END
  END kst[2]
  PIN kst[3]
    DIRECTION OUTPUT ;
    USE SIGNAL ;
    PORT
      LAYER M5 ;
        RECT  16.416 0 16.44 0.084 ;
    END
  END kst[3]
  PIN kst[4]
    DIRECTION OUTPUT ;
    USE SIGNAL ;
    PORT
      LAYER M5 ;
        RECT  16.56 0 16.584 0.084 ;
    END
  END kst[4]
  PIN kst[5]
    DIRECTION OUTPUT ;
    USE SIGNAL ;
    PORT
      LAYER M5 ;
        RECT  16.704 0 16.728 0.084 ;
    END
  END kst[5]
  PIN kst[6]
    DIRECTION OUTPUT ;
    USE SIGNAL ;
    PORT
      LAYER M5 ;
        RECT  16.848 0 16.872 0.084 ;
    END
  END kst[6]
  PIN kst[7]
    DIRECTION OUTPUT ;
    USE SIGNAL ;
    PORT
      LAYER M5 ;
        RECT  16.992 0 17.016 0.084 ;
    END
  END kst[7]
  PIN kst[8]
    DIRECTION OUTPUT ;
    USE SIGNAL ;
    PORT
      LAYER M5 ;
        RECT  17.136 0 17.16 0.084 ;
    END
  END kst[8]
  PIN kst[9]
    DIRECTION OUTPUT ;
    USE SIGNAL ;
    PORT
      LAYER M5 ;
        RECT  17.28 0 17.304 0.084 ;
    END
  END kst[9]
  PIN kvn_word_tag[0]
    DIRECTION INPUT ;
    USE SIGNAL ;
    PORT
      LAYER M5 ;
        RECT  16.56 29.076 16.584 29.16 ;
    END
  END kvn_word_tag[0]
  PIN kvn_word_tag[10]
    DIRECTION INPUT ;
    USE SIGNAL ;
    PORT
      LAYER M5 ;
        RECT  18 29.076 18.024 29.16 ;
    END
  END kvn_word_tag[10]
  PIN kvn_word_tag[1]
    DIRECTION INPUT ;
    USE SIGNAL ;
    PORT
      LAYER M5 ;
        RECT  16.704 29.076 16.728 29.16 ;
    END
  END kvn_word_tag[1]
  PIN kvn_word_tag[2]
    DIRECTION INPUT ;
    USE SIGNAL ;
    PORT
      LAYER M5 ;
        RECT  16.848 29.076 16.872 29.16 ;
    END
  END kvn_word_tag[2]
  PIN kvn_word_tag[3]
    DIRECTION INPUT ;
    USE SIGNAL ;
    PORT
      LAYER M5 ;
        RECT  16.992 29.076 17.016 29.16 ;
    END
  END kvn_word_tag[3]
  PIN kvn_word_tag[4]
    DIRECTION INPUT ;
    USE SIGNAL ;
    PORT
      LAYER M5 ;
        RECT  17.136 29.076 17.16 29.16 ;
    END
  END kvn_word_tag[4]
  PIN kvn_word_tag[5]
    DIRECTION INPUT ;
    USE SIGNAL ;
    PORT
      LAYER M5 ;
        RECT  17.28 29.076 17.304 29.16 ;
    END
  END kvn_word_tag[5]
  PIN kvn_word_tag[6]
    DIRECTION INPUT ;
    USE SIGNAL ;
    PORT
      LAYER M5 ;
        RECT  17.424 29.076 17.448 29.16 ;
    END
  END kvn_word_tag[6]
  PIN kvn_word_tag[7]
    DIRECTION INPUT ;
    USE SIGNAL ;
    PORT
      LAYER M5 ;
        RECT  17.568 29.076 17.592 29.16 ;
    END
  END kvn_word_tag[7]
  PIN kvn_word_tag[8]
    DIRECTION INPUT ;
    USE SIGNAL ;
    PORT
      LAYER M5 ;
        RECT  17.712 29.076 17.736 29.16 ;
    END
  END kvn_word_tag[8]
  PIN kvn_word_tag[9]
    DIRECTION INPUT ;
    USE SIGNAL ;
    PORT
      LAYER M5 ;
        RECT  17.856 29.076 17.88 29.16 ;
    END
  END kvn_word_tag[9]
  PIN kvn_word_valid
    DIRECTION INPUT ;
    USE SIGNAL ;
    PORT
      LAYER M5 ;
        RECT  18.144 29.076 18.168 29.16 ;
    END
  END kvn_word_valid
  PIN lp_ctx_t[0]
    DIRECTION INPUT ;
    USE SIGNAL ;
    PORT
      LAYER M5 ;
        RECT  18.288 29.076 18.312 29.16 ;
    END
  END lp_ctx_t[0]
  PIN lp_ctx_t[10]
    DIRECTION INPUT ;
    USE SIGNAL ;
    PORT
      LAYER M5 ;
        RECT  19.728 29.076 19.752 29.16 ;
    END
  END lp_ctx_t[10]
  PIN lp_ctx_t[11]
    DIRECTION INPUT ;
    USE SIGNAL ;
    PORT
      LAYER M5 ;
        RECT  19.872 29.076 19.896 29.16 ;
    END
  END lp_ctx_t[11]
  PIN lp_ctx_t[12]
    DIRECTION INPUT ;
    USE SIGNAL ;
    PORT
      LAYER M5 ;
        RECT  20.016 29.076 20.04 29.16 ;
    END
  END lp_ctx_t[12]
  PIN lp_ctx_t[13]
    DIRECTION INPUT ;
    USE SIGNAL ;
    PORT
      LAYER M5 ;
        RECT  20.16 29.076 20.184 29.16 ;
    END
  END lp_ctx_t[13]
  PIN lp_ctx_t[1]
    DIRECTION INPUT ;
    USE SIGNAL ;
    PORT
      LAYER M5 ;
        RECT  18.432 29.076 18.456 29.16 ;
    END
  END lp_ctx_t[1]
  PIN lp_ctx_t[2]
    DIRECTION INPUT ;
    USE SIGNAL ;
    PORT
      LAYER M5 ;
        RECT  18.576 29.076 18.6 29.16 ;
    END
  END lp_ctx_t[2]
  PIN lp_ctx_t[3]
    DIRECTION INPUT ;
    USE SIGNAL ;
    PORT
      LAYER M5 ;
        RECT  18.72 29.076 18.744 29.16 ;
    END
  END lp_ctx_t[3]
  PIN lp_ctx_t[4]
    DIRECTION INPUT ;
    USE SIGNAL ;
    PORT
      LAYER M5 ;
        RECT  18.864 29.076 18.888 29.16 ;
    END
  END lp_ctx_t[4]
  PIN lp_ctx_t[5]
    DIRECTION INPUT ;
    USE SIGNAL ;
    PORT
      LAYER M5 ;
        RECT  19.008 29.076 19.032 29.16 ;
    END
  END lp_ctx_t[5]
  PIN lp_ctx_t[6]
    DIRECTION INPUT ;
    USE SIGNAL ;
    PORT
      LAYER M5 ;
        RECT  19.152 29.076 19.176 29.16 ;
    END
  END lp_ctx_t[6]
  PIN lp_ctx_t[7]
    DIRECTION INPUT ;
    USE SIGNAL ;
    PORT
      LAYER M5 ;
        RECT  19.296 29.076 19.32 29.16 ;
    END
  END lp_ctx_t[7]
  PIN lp_ctx_t[8]
    DIRECTION INPUT ;
    USE SIGNAL ;
    PORT
      LAYER M5 ;
        RECT  19.44 29.076 19.464 29.16 ;
    END
  END lp_ctx_t[8]
  PIN lp_ctx_t[9]
    DIRECTION INPUT ;
    USE SIGNAL ;
    PORT
      LAYER M5 ;
        RECT  19.584 29.076 19.608 29.16 ;
    END
  END lp_ctx_t[9]
  PIN lp_layer[0]
    DIRECTION INPUT ;
    USE SIGNAL ;
    PORT
      LAYER M5 ;
        RECT  20.304 29.076 20.328 29.16 ;
    END
  END lp_layer[0]
  PIN lp_layer[1]
    DIRECTION INPUT ;
    USE SIGNAL ;
    PORT
      LAYER M5 ;
        RECT  20.448 29.076 20.472 29.16 ;
    END
  END lp_layer[1]
  PIN lp_layer[2]
    DIRECTION INPUT ;
    USE SIGNAL ;
    PORT
      LAYER M5 ;
        RECT  20.592 29.076 20.616 29.16 ;
    END
  END lp_layer[2]
  PIN lp_layer[3]
    DIRECTION INPUT ;
    USE SIGNAL ;
    PORT
      LAYER M5 ;
        RECT  20.736 29.076 20.76 29.16 ;
    END
  END lp_layer[3]
  PIN lp_layer[4]
    DIRECTION INPUT ;
    USE SIGNAL ;
    PORT
      LAYER M5 ;
        RECT  20.88 29.076 20.904 29.16 ;
    END
  END lp_layer[4]
  PIN lp_layer[5]
    DIRECTION INPUT ;
    USE SIGNAL ;
    PORT
      LAYER M5 ;
        RECT  21.024 29.076 21.048 29.16 ;
    END
  END lp_layer[5]
  PIN lp_run
    DIRECTION INPUT ;
    USE SIGNAL ;
    PORT
      LAYER M5 ;
        RECT  21.168 29.076 21.192 29.16 ;
    END
  END lp_run
  PIN rst_n
    DIRECTION INPUT ;
    USE SIGNAL ;
    PORT
      LAYER M5 ;
        RECT  17.424 0 17.448 0.084 ;
    END
  END rst_n
  PIN s_kidx[0]
    DIRECTION OUTPUT ;
    USE SIGNAL ;
    PORT
      LAYER M5 ;
        RECT  21.312 29.076 21.336 29.16 ;
    END
  END s_kidx[0]
  PIN s_kidx[1]
    DIRECTION OUTPUT ;
    USE SIGNAL ;
    PORT
      LAYER M5 ;
        RECT  10.656 29.076 10.68 29.16 ;
    END
  END s_kidx[1]
  PIN s_kidx[2]
    DIRECTION OUTPUT ;
    USE SIGNAL ;
    PORT
      LAYER M5 ;
        RECT  10.8 29.076 10.824 29.16 ;
    END
  END s_kidx[2]
  PIN s_kpop
    DIRECTION OUTPUT ;
    USE SIGNAL ;
    PORT
      LAYER M5 ;
        RECT  10.944 29.076 10.968 29.16 ;
    END
  END s_kpop
  PIN s_kwgo
    DIRECTION OUTPUT ;
    USE SIGNAL ;
    PORT
      LAYER M5 ;
        RECT  11.088 29.076 11.112 29.16 ;
    END
  END s_kwgo
  PIN s_kwn[0]
    DIRECTION OUTPUT ;
    USE SIGNAL ;
    PORT
      LAYER M5 ;
        RECT  11.232 29.076 11.256 29.16 ;
    END
  END s_kwn[0]
  PIN s_kwn[1]
    DIRECTION OUTPUT ;
    USE SIGNAL ;
    PORT
      LAYER M5 ;
        RECT  11.376 29.076 11.4 29.16 ;
    END
  END s_kwn[1]
  PIN s_qpop
    DIRECTION OUTPUT ;
    USE SIGNAL ;
    PORT
      LAYER M5 ;
        RECT  11.52 29.076 11.544 29.16 ;
    END
  END s_qpop
  PIN svc_h[0]
    DIRECTION INPUT ;
    USE SIGNAL ;
    PORT
      LAYER M5 ;
        RECT  17.568 0 17.592 0.084 ;
    END
  END svc_h[0]
  PIN svc_h[10]
    DIRECTION INPUT ;
    USE SIGNAL ;
    PORT
      LAYER M5 ;
        RECT  19.008 0 19.032 0.084 ;
    END
  END svc_h[10]
  PIN svc_h[11]
    DIRECTION INPUT ;
    USE SIGNAL ;
    PORT
      LAYER M5 ;
        RECT  58.32 0 58.344 0.084 ;
    END
  END svc_h[11]
  PIN svc_h[12]
    DIRECTION INPUT ;
    USE SIGNAL ;
    PORT
      LAYER M5 ;
        RECT  58.464 0 58.488 0.084 ;
    END
  END svc_h[12]
  PIN svc_h[13]
    DIRECTION INPUT ;
    USE SIGNAL ;
    PORT
      LAYER M5 ;
        RECT  58.608 0 58.632 0.084 ;
    END
  END svc_h[13]
  PIN svc_h[14]
    DIRECTION INPUT ;
    USE SIGNAL ;
    PORT
      LAYER M5 ;
        RECT  58.752 0 58.776 0.084 ;
    END
  END svc_h[14]
  PIN svc_h[15]
    DIRECTION INPUT ;
    USE SIGNAL ;
    PORT
      LAYER M5 ;
        RECT  58.896 0 58.92 0.084 ;
    END
  END svc_h[15]
  PIN svc_h[16]
    DIRECTION INPUT ;
    USE SIGNAL ;
    PORT
      LAYER M5 ;
        RECT  59.04 0 59.064 0.084 ;
    END
  END svc_h[16]
  PIN svc_h[17]
    DIRECTION INPUT ;
    USE SIGNAL ;
    PORT
      LAYER M5 ;
        RECT  59.184 0 59.208 0.084 ;
    END
  END svc_h[17]
  PIN svc_h[18]
    DIRECTION INPUT ;
    USE SIGNAL ;
    PORT
      LAYER M5 ;
        RECT  59.328 0 59.352 0.084 ;
    END
  END svc_h[18]
  PIN svc_h[19]
    DIRECTION INPUT ;
    USE SIGNAL ;
    PORT
      LAYER M5 ;
        RECT  59.472 0 59.496 0.084 ;
    END
  END svc_h[19]
  PIN svc_h[1]
    DIRECTION INPUT ;
    USE SIGNAL ;
    PORT
      LAYER M5 ;
        RECT  17.712 0 17.736 0.084 ;
    END
  END svc_h[1]
  PIN svc_h[20]
    DIRECTION INPUT ;
    USE SIGNAL ;
    PORT
      LAYER M5 ;
        RECT  59.616 0 59.64 0.084 ;
    END
  END svc_h[20]
  PIN svc_h[21]
    DIRECTION INPUT ;
    USE SIGNAL ;
    PORT
      LAYER M5 ;
        RECT  59.76 0 59.784 0.084 ;
    END
  END svc_h[21]
  PIN svc_h[22]
    DIRECTION INPUT ;
    USE SIGNAL ;
    PORT
      LAYER M5 ;
        RECT  59.904 0 59.928 0.084 ;
    END
  END svc_h[22]
  PIN svc_h[23]
    DIRECTION INPUT ;
    USE SIGNAL ;
    PORT
      LAYER M5 ;
        RECT  60.048 0 60.072 0.084 ;
    END
  END svc_h[23]
  PIN svc_h[24]
    DIRECTION INPUT ;
    USE SIGNAL ;
    PORT
      LAYER M5 ;
        RECT  60.192 0 60.216 0.084 ;
    END
  END svc_h[24]
  PIN svc_h[25]
    DIRECTION INPUT ;
    USE SIGNAL ;
    PORT
      LAYER M5 ;
        RECT  60.336 0 60.36 0.084 ;
    END
  END svc_h[25]
  PIN svc_h[26]
    DIRECTION INPUT ;
    USE SIGNAL ;
    PORT
      LAYER M5 ;
        RECT  60.48 0 60.504 0.084 ;
    END
  END svc_h[26]
  PIN svc_h[27]
    DIRECTION INPUT ;
    USE SIGNAL ;
    PORT
      LAYER M5 ;
        RECT  60.624 0 60.648 0.084 ;
    END
  END svc_h[27]
  PIN svc_h[28]
    DIRECTION INPUT ;
    USE SIGNAL ;
    PORT
      LAYER M5 ;
        RECT  60.768 0 60.792 0.084 ;
    END
  END svc_h[28]
  PIN svc_h[29]
    DIRECTION INPUT ;
    USE SIGNAL ;
    PORT
      LAYER M5 ;
        RECT  60.912 0 60.936 0.084 ;
    END
  END svc_h[29]
  PIN svc_h[2]
    DIRECTION INPUT ;
    USE SIGNAL ;
    PORT
      LAYER M5 ;
        RECT  17.856 0 17.88 0.084 ;
    END
  END svc_h[2]
  PIN svc_h[30]
    DIRECTION INPUT ;
    USE SIGNAL ;
    PORT
      LAYER M5 ;
        RECT  61.056 0 61.08 0.084 ;
    END
  END svc_h[30]
  PIN svc_h[31]
    DIRECTION INPUT ;
    USE SIGNAL ;
    PORT
      LAYER M5 ;
        RECT  61.2 0 61.224 0.084 ;
    END
  END svc_h[31]
  PIN svc_h[32]
    DIRECTION INPUT ;
    USE SIGNAL ;
    PORT
      LAYER M5 ;
        RECT  61.344 0 61.368 0.084 ;
    END
  END svc_h[32]
  PIN svc_h[33]
    DIRECTION INPUT ;
    USE SIGNAL ;
    PORT
      LAYER M5 ;
        RECT  61.488 0 61.512 0.084 ;
    END
  END svc_h[33]
  PIN svc_h[34]
    DIRECTION INPUT ;
    USE SIGNAL ;
    PORT
      LAYER M5 ;
        RECT  61.632 0 61.656 0.084 ;
    END
  END svc_h[34]
  PIN svc_h[35]
    DIRECTION INPUT ;
    USE SIGNAL ;
    PORT
      LAYER M5 ;
        RECT  61.776 0 61.8 0.084 ;
    END
  END svc_h[35]
  PIN svc_h[36]
    DIRECTION INPUT ;
    USE SIGNAL ;
    PORT
      LAYER M5 ;
        RECT  61.92 0 61.944 0.084 ;
    END
  END svc_h[36]
  PIN svc_h[37]
    DIRECTION INPUT ;
    USE SIGNAL ;
    PORT
      LAYER M5 ;
        RECT  62.064 0 62.088 0.084 ;
    END
  END svc_h[37]
  PIN svc_h[38]
    DIRECTION INPUT ;
    USE SIGNAL ;
    PORT
      LAYER M5 ;
        RECT  62.208 0 62.232 0.084 ;
    END
  END svc_h[38]
  PIN svc_h[39]
    DIRECTION INPUT ;
    USE SIGNAL ;
    PORT
      LAYER M5 ;
        RECT  62.352 0 62.376 0.084 ;
    END
  END svc_h[39]
  PIN svc_h[3]
    DIRECTION INPUT ;
    USE SIGNAL ;
    PORT
      LAYER M5 ;
        RECT  18 0 18.024 0.084 ;
    END
  END svc_h[3]
  PIN svc_h[40]
    DIRECTION INPUT ;
    USE SIGNAL ;
    PORT
      LAYER M5 ;
        RECT  62.496 0 62.52 0.084 ;
    END
  END svc_h[40]
  PIN svc_h[41]
    DIRECTION INPUT ;
    USE SIGNAL ;
    PORT
      LAYER M5 ;
        RECT  62.64 0 62.664 0.084 ;
    END
  END svc_h[41]
  PIN svc_h[42]
    DIRECTION INPUT ;
    USE SIGNAL ;
    PORT
      LAYER M5 ;
        RECT  62.784 0 62.808 0.084 ;
    END
  END svc_h[42]
  PIN svc_h[43]
    DIRECTION INPUT ;
    USE SIGNAL ;
    PORT
      LAYER M5 ;
        RECT  43.344 0 43.368 0.084 ;
    END
  END svc_h[43]
  PIN svc_h[44]
    DIRECTION INPUT ;
    USE SIGNAL ;
    PORT
      LAYER M5 ;
        RECT  43.488 0 43.512 0.084 ;
    END
  END svc_h[44]
  PIN svc_h[45]
    DIRECTION INPUT ;
    USE SIGNAL ;
    PORT
      LAYER M5 ;
        RECT  43.632 0 43.656 0.084 ;
    END
  END svc_h[45]
  PIN svc_h[46]
    DIRECTION INPUT ;
    USE SIGNAL ;
    PORT
      LAYER M5 ;
        RECT  43.776 0 43.8 0.084 ;
    END
  END svc_h[46]
  PIN svc_h[47]
    DIRECTION INPUT ;
    USE SIGNAL ;
    PORT
      LAYER M5 ;
        RECT  43.92 0 43.944 0.084 ;
    END
  END svc_h[47]
  PIN svc_h[48]
    DIRECTION INPUT ;
    USE SIGNAL ;
    PORT
      LAYER M5 ;
        RECT  44.064 0 44.088 0.084 ;
    END
  END svc_h[48]
  PIN svc_h[49]
    DIRECTION INPUT ;
    USE SIGNAL ;
    PORT
      LAYER M5 ;
        RECT  44.208 0 44.232 0.084 ;
    END
  END svc_h[49]
  PIN svc_h[4]
    DIRECTION INPUT ;
    USE SIGNAL ;
    PORT
      LAYER M5 ;
        RECT  18.144 0 18.168 0.084 ;
    END
  END svc_h[4]
  PIN svc_h[50]
    DIRECTION INPUT ;
    USE SIGNAL ;
    PORT
      LAYER M5 ;
        RECT  44.352 0 44.376 0.084 ;
    END
  END svc_h[50]
  PIN svc_h[51]
    DIRECTION INPUT ;
    USE SIGNAL ;
    PORT
      LAYER M5 ;
        RECT  44.496 0 44.52 0.084 ;
    END
  END svc_h[51]
  PIN svc_h[52]
    DIRECTION INPUT ;
    USE SIGNAL ;
    PORT
      LAYER M5 ;
        RECT  44.64 0 44.664 0.084 ;
    END
  END svc_h[52]
  PIN svc_h[53]
    DIRECTION INPUT ;
    USE SIGNAL ;
    PORT
      LAYER M5 ;
        RECT  44.784 0 44.808 0.084 ;
    END
  END svc_h[53]
  PIN svc_h[54]
    DIRECTION INPUT ;
    USE SIGNAL ;
    PORT
      LAYER M5 ;
        RECT  44.928 0 44.952 0.084 ;
    END
  END svc_h[54]
  PIN svc_h[55]
    DIRECTION INPUT ;
    USE SIGNAL ;
    PORT
      LAYER M5 ;
        RECT  45.072 0 45.096 0.084 ;
    END
  END svc_h[55]
  PIN svc_h[56]
    DIRECTION INPUT ;
    USE SIGNAL ;
    PORT
      LAYER M5 ;
        RECT  45.216 0 45.24 0.084 ;
    END
  END svc_h[56]
  PIN svc_h[57]
    DIRECTION INPUT ;
    USE SIGNAL ;
    PORT
      LAYER M5 ;
        RECT  45.36 0 45.384 0.084 ;
    END
  END svc_h[57]
  PIN svc_h[58]
    DIRECTION INPUT ;
    USE SIGNAL ;
    PORT
      LAYER M5 ;
        RECT  45.504 0 45.528 0.084 ;
    END
  END svc_h[58]
  PIN svc_h[59]
    DIRECTION INPUT ;
    USE SIGNAL ;
    PORT
      LAYER M5 ;
        RECT  45.648 0 45.672 0.084 ;
    END
  END svc_h[59]
  PIN svc_h[5]
    DIRECTION INPUT ;
    USE SIGNAL ;
    PORT
      LAYER M5 ;
        RECT  18.288 0 18.312 0.084 ;
    END
  END svc_h[5]
  PIN svc_h[60]
    DIRECTION INPUT ;
    USE SIGNAL ;
    PORT
      LAYER M5 ;
        RECT  45.792 0 45.816 0.084 ;
    END
  END svc_h[60]
  PIN svc_h[61]
    DIRECTION INPUT ;
    USE SIGNAL ;
    PORT
      LAYER M5 ;
        RECT  45.936 0 45.96 0.084 ;
    END
  END svc_h[61]
  PIN svc_h[62]
    DIRECTION INPUT ;
    USE SIGNAL ;
    PORT
      LAYER M5 ;
        RECT  46.08 0 46.104 0.084 ;
    END
  END svc_h[62]
  PIN svc_h[63]
    DIRECTION INPUT ;
    USE SIGNAL ;
    PORT
      LAYER M5 ;
        RECT  46.224 0 46.248 0.084 ;
    END
  END svc_h[63]
  PIN svc_h[64]
    DIRECTION INPUT ;
    USE SIGNAL ;
    PORT
      LAYER M5 ;
        RECT  46.368 0 46.392 0.084 ;
    END
  END svc_h[64]
  PIN svc_h[65]
    DIRECTION INPUT ;
    USE SIGNAL ;
    PORT
      LAYER M5 ;
        RECT  46.512 0 46.536 0.084 ;
    END
  END svc_h[65]
  PIN svc_h[66]
    DIRECTION INPUT ;
    USE SIGNAL ;
    PORT
      LAYER M5 ;
        RECT  46.656 0 46.68 0.084 ;
    END
  END svc_h[66]
  PIN svc_h[67]
    DIRECTION INPUT ;
    USE SIGNAL ;
    PORT
      LAYER M5 ;
        RECT  46.8 0 46.824 0.084 ;
    END
  END svc_h[67]
  PIN svc_h[68]
    DIRECTION INPUT ;
    USE SIGNAL ;
    PORT
      LAYER M5 ;
        RECT  46.944 0 46.968 0.084 ;
    END
  END svc_h[68]
  PIN svc_h[69]
    DIRECTION INPUT ;
    USE SIGNAL ;
    PORT
      LAYER M5 ;
        RECT  47.088 0 47.112 0.084 ;
    END
  END svc_h[69]
  PIN svc_h[6]
    DIRECTION INPUT ;
    USE SIGNAL ;
    PORT
      LAYER M5 ;
        RECT  18.432 0 18.456 0.084 ;
    END
  END svc_h[6]
  PIN svc_h[70]
    DIRECTION INPUT ;
    USE SIGNAL ;
    PORT
      LAYER M5 ;
        RECT  47.232 0 47.256 0.084 ;
    END
  END svc_h[70]
  PIN svc_h[71]
    DIRECTION INPUT ;
    USE SIGNAL ;
    PORT
      LAYER M5 ;
        RECT  47.376 0 47.4 0.084 ;
    END
  END svc_h[71]
  PIN svc_h[72]
    DIRECTION INPUT ;
    USE SIGNAL ;
    PORT
      LAYER M5 ;
        RECT  47.52 0 47.544 0.084 ;
    END
  END svc_h[72]
  PIN svc_h[73]
    DIRECTION INPUT ;
    USE SIGNAL ;
    PORT
      LAYER M5 ;
        RECT  47.664 0 47.688 0.084 ;
    END
  END svc_h[73]
  PIN svc_h[74]
    DIRECTION INPUT ;
    USE SIGNAL ;
    PORT
      LAYER M5 ;
        RECT  47.808 0 47.832 0.084 ;
    END
  END svc_h[74]
  PIN svc_h[75]
    DIRECTION INPUT ;
    USE SIGNAL ;
    PORT
      LAYER M5 ;
        RECT  47.952 0 47.976 0.084 ;
    END
  END svc_h[75]
  PIN svc_h[76]
    DIRECTION INPUT ;
    USE SIGNAL ;
    PORT
      LAYER M5 ;
        RECT  48.096 0 48.12 0.084 ;
    END
  END svc_h[76]
  PIN svc_h[77]
    DIRECTION INPUT ;
    USE SIGNAL ;
    PORT
      LAYER M5 ;
        RECT  48.24 0 48.264 0.084 ;
    END
  END svc_h[77]
  PIN svc_h[78]
    DIRECTION INPUT ;
    USE SIGNAL ;
    PORT
      LAYER M5 ;
        RECT  48.384 0 48.408 0.084 ;
    END
  END svc_h[78]
  PIN svc_h[79]
    DIRECTION INPUT ;
    USE SIGNAL ;
    PORT
      LAYER M5 ;
        RECT  48.528 0 48.552 0.084 ;
    END
  END svc_h[79]
  PIN svc_h[7]
    DIRECTION INPUT ;
    USE SIGNAL ;
    PORT
      LAYER M5 ;
        RECT  18.576 0 18.6 0.084 ;
    END
  END svc_h[7]
  PIN svc_h[80]
    DIRECTION INPUT ;
    USE SIGNAL ;
    PORT
      LAYER M5 ;
        RECT  48.672 0 48.696 0.084 ;
    END
  END svc_h[80]
  PIN svc_h[81]
    DIRECTION INPUT ;
    USE SIGNAL ;
    PORT
      LAYER M5 ;
        RECT  48.816 0 48.84 0.084 ;
    END
  END svc_h[81]
  PIN svc_h[82]
    DIRECTION INPUT ;
    USE SIGNAL ;
    PORT
      LAYER M5 ;
        RECT  48.96 0 48.984 0.084 ;
    END
  END svc_h[82]
  PIN svc_h[83]
    DIRECTION INPUT ;
    USE SIGNAL ;
    PORT
      LAYER M5 ;
        RECT  49.104 0 49.128 0.084 ;
    END
  END svc_h[83]
  PIN svc_h[84]
    DIRECTION INPUT ;
    USE SIGNAL ;
    PORT
      LAYER M5 ;
        RECT  49.248 0 49.272 0.084 ;
    END
  END svc_h[84]
  PIN svc_h[85]
    DIRECTION INPUT ;
    USE SIGNAL ;
    PORT
      LAYER M5 ;
        RECT  49.392 0 49.416 0.084 ;
    END
  END svc_h[85]
  PIN svc_h[86]
    DIRECTION INPUT ;
    USE SIGNAL ;
    PORT
      LAYER M5 ;
        RECT  49.536 0 49.56 0.084 ;
    END
  END svc_h[86]
  PIN svc_h[87]
    DIRECTION INPUT ;
    USE SIGNAL ;
    PORT
      LAYER M5 ;
        RECT  49.68 0 49.704 0.084 ;
    END
  END svc_h[87]
  PIN svc_h[8]
    DIRECTION INPUT ;
    USE SIGNAL ;
    PORT
      LAYER M5 ;
        RECT  18.72 0 18.744 0.084 ;
    END
  END svc_h[8]
  PIN svc_h[9]
    DIRECTION INPUT ;
    USE SIGNAL ;
    PORT
      LAYER M5 ;
        RECT  18.864 0 18.888 0.084 ;
    END
  END svc_h[9]
  PIN tk[0]
    DIRECTION OUTPUT ;
    USE SIGNAL ;
    PORT
      LAYER M5 ;
        RECT  49.824 0 49.848 0.084 ;
    END
  END tk[0]
  PIN tk[10]
    DIRECTION OUTPUT ;
    USE SIGNAL ;
    PORT
      LAYER M5 ;
        RECT  51.264 0 51.288 0.084 ;
    END
  END tk[10]
  PIN tk[11]
    DIRECTION OUTPUT ;
    USE SIGNAL ;
    PORT
      LAYER M5 ;
        RECT  51.408 0 51.432 0.084 ;
    END
  END tk[11]
  PIN tk[12]
    DIRECTION OUTPUT ;
    USE SIGNAL ;
    PORT
      LAYER M5 ;
        RECT  51.552 0 51.576 0.084 ;
    END
  END tk[12]
  PIN tk[13]
    DIRECTION OUTPUT ;
    USE SIGNAL ;
    PORT
      LAYER M5 ;
        RECT  51.696 0 51.72 0.084 ;
    END
  END tk[13]
  PIN tk[14]
    DIRECTION OUTPUT ;
    USE SIGNAL ;
    PORT
      LAYER M5 ;
        RECT  51.84 0 51.864 0.084 ;
    END
  END tk[14]
  PIN tk[15]
    DIRECTION OUTPUT ;
    USE SIGNAL ;
    PORT
      LAYER M5 ;
        RECT  51.984 0 52.008 0.084 ;
    END
  END tk[15]
  PIN tk[16]
    DIRECTION OUTPUT ;
    USE SIGNAL ;
    PORT
      LAYER M5 ;
        RECT  52.128 0 52.152 0.084 ;
    END
  END tk[16]
  PIN tk[17]
    DIRECTION OUTPUT ;
    USE SIGNAL ;
    PORT
      LAYER M5 ;
        RECT  52.272 0 52.296 0.084 ;
    END
  END tk[17]
  PIN tk[18]
    DIRECTION OUTPUT ;
    USE SIGNAL ;
    PORT
      LAYER M5 ;
        RECT  52.416 0 52.44 0.084 ;
    END
  END tk[18]
  PIN tk[19]
    DIRECTION OUTPUT ;
    USE SIGNAL ;
    PORT
      LAYER M5 ;
        RECT  52.56 0 52.584 0.084 ;
    END
  END tk[19]
  PIN tk[1]
    DIRECTION OUTPUT ;
    USE SIGNAL ;
    PORT
      LAYER M5 ;
        RECT  49.968 0 49.992 0.084 ;
    END
  END tk[1]
  PIN tk[20]
    DIRECTION OUTPUT ;
    USE SIGNAL ;
    PORT
      LAYER M5 ;
        RECT  52.704 0 52.728 0.084 ;
    END
  END tk[20]
  PIN tk[21]
    DIRECTION OUTPUT ;
    USE SIGNAL ;
    PORT
      LAYER M5 ;
        RECT  52.848 0 52.872 0.084 ;
    END
  END tk[21]
  PIN tk[22]
    DIRECTION OUTPUT ;
    USE SIGNAL ;
    PORT
      LAYER M5 ;
        RECT  52.992 0 53.016 0.084 ;
    END
  END tk[22]
  PIN tk[23]
    DIRECTION OUTPUT ;
    USE SIGNAL ;
    PORT
      LAYER M5 ;
        RECT  53.136 0 53.16 0.084 ;
    END
  END tk[23]
  PIN tk[24]
    DIRECTION OUTPUT ;
    USE SIGNAL ;
    PORT
      LAYER M5 ;
        RECT  53.28 0 53.304 0.084 ;
    END
  END tk[24]
  PIN tk[25]
    DIRECTION OUTPUT ;
    USE SIGNAL ;
    PORT
      LAYER M5 ;
        RECT  53.424 0 53.448 0.084 ;
    END
  END tk[25]
  PIN tk[26]
    DIRECTION OUTPUT ;
    USE SIGNAL ;
    PORT
      LAYER M5 ;
        RECT  53.568 0 53.592 0.084 ;
    END
  END tk[26]
  PIN tk[27]
    DIRECTION OUTPUT ;
    USE SIGNAL ;
    PORT
      LAYER M5 ;
        RECT  53.712 0 53.736 0.084 ;
    END
  END tk[27]
  PIN tk[28]
    DIRECTION OUTPUT ;
    USE SIGNAL ;
    PORT
      LAYER M5 ;
        RECT  53.856 0 53.88 0.084 ;
    END
  END tk[28]
  PIN tk[29]
    DIRECTION OUTPUT ;
    USE SIGNAL ;
    PORT
      LAYER M5 ;
        RECT  54 0 54.024 0.084 ;
    END
  END tk[29]
  PIN tk[2]
    DIRECTION OUTPUT ;
    USE SIGNAL ;
    PORT
      LAYER M5 ;
        RECT  50.112 0 50.136 0.084 ;
    END
  END tk[2]
  PIN tk[30]
    DIRECTION OUTPUT ;
    USE SIGNAL ;
    PORT
      LAYER M5 ;
        RECT  54.144 0 54.168 0.084 ;
    END
  END tk[30]
  PIN tk[31]
    DIRECTION OUTPUT ;
    USE SIGNAL ;
    PORT
      LAYER M5 ;
        RECT  54.288 0 54.312 0.084 ;
    END
  END tk[31]
  PIN tk[32]
    DIRECTION OUTPUT ;
    USE SIGNAL ;
    PORT
      LAYER M5 ;
        RECT  54.432 0 54.456 0.084 ;
    END
  END tk[32]
  PIN tk[33]
    DIRECTION OUTPUT ;
    USE SIGNAL ;
    PORT
      LAYER M5 ;
        RECT  54.576 0 54.6 0.084 ;
    END
  END tk[33]
  PIN tk[34]
    DIRECTION OUTPUT ;
    USE SIGNAL ;
    PORT
      LAYER M5 ;
        RECT  54.72 0 54.744 0.084 ;
    END
  END tk[34]
  PIN tk[35]
    DIRECTION OUTPUT ;
    USE SIGNAL ;
    PORT
      LAYER M5 ;
        RECT  54.864 0 54.888 0.084 ;
    END
  END tk[35]
  PIN tk[36]
    DIRECTION OUTPUT ;
    USE SIGNAL ;
    PORT
      LAYER M5 ;
        RECT  55.008 0 55.032 0.084 ;
    END
  END tk[36]
  PIN tk[37]
    DIRECTION OUTPUT ;
    USE SIGNAL ;
    PORT
      LAYER M5 ;
        RECT  55.152 0 55.176 0.084 ;
    END
  END tk[37]
  PIN tk[38]
    DIRECTION OUTPUT ;
    USE SIGNAL ;
    PORT
      LAYER M5 ;
        RECT  55.296 0 55.32 0.084 ;
    END
  END tk[38]
  PIN tk[39]
    DIRECTION OUTPUT ;
    USE SIGNAL ;
    PORT
      LAYER M5 ;
        RECT  55.44 0 55.464 0.084 ;
    END
  END tk[39]
  PIN tk[3]
    DIRECTION OUTPUT ;
    USE SIGNAL ;
    PORT
      LAYER M5 ;
        RECT  50.256 0 50.28 0.084 ;
    END
  END tk[3]
  PIN tk[40]
    DIRECTION OUTPUT ;
    USE SIGNAL ;
    PORT
      LAYER M5 ;
        RECT  55.584 0 55.608 0.084 ;
    END
  END tk[40]
  PIN tk[41]
    DIRECTION OUTPUT ;
    USE SIGNAL ;
    PORT
      LAYER M5 ;
        RECT  55.728 0 55.752 0.084 ;
    END
  END tk[41]
  PIN tk[42]
    DIRECTION OUTPUT ;
    USE SIGNAL ;
    PORT
      LAYER M5 ;
        RECT  55.872 0 55.896 0.084 ;
    END
  END tk[42]
  PIN tk[43]
    DIRECTION OUTPUT ;
    USE SIGNAL ;
    PORT
      LAYER M5 ;
        RECT  56.016 0 56.04 0.084 ;
    END
  END tk[43]
  PIN tk[44]
    DIRECTION OUTPUT ;
    USE SIGNAL ;
    PORT
      LAYER M5 ;
        RECT  56.16 0 56.184 0.084 ;
    END
  END tk[44]
  PIN tk[45]
    DIRECTION OUTPUT ;
    USE SIGNAL ;
    PORT
      LAYER M5 ;
        RECT  56.304 0 56.328 0.084 ;
    END
  END tk[45]
  PIN tk[46]
    DIRECTION OUTPUT ;
    USE SIGNAL ;
    PORT
      LAYER M5 ;
        RECT  56.448 0 56.472 0.084 ;
    END
  END tk[46]
  PIN tk[47]
    DIRECTION OUTPUT ;
    USE SIGNAL ;
    PORT
      LAYER M5 ;
        RECT  56.592 0 56.616 0.084 ;
    END
  END tk[47]
  PIN tk[48]
    DIRECTION OUTPUT ;
    USE SIGNAL ;
    PORT
      LAYER M5 ;
        RECT  56.736 0 56.76 0.084 ;
    END
  END tk[48]
  PIN tk[49]
    DIRECTION OUTPUT ;
    USE SIGNAL ;
    PORT
      LAYER M5 ;
        RECT  56.88 0 56.904 0.084 ;
    END
  END tk[49]
  PIN tk[4]
    DIRECTION OUTPUT ;
    USE SIGNAL ;
    PORT
      LAYER M5 ;
        RECT  50.4 0 50.424 0.084 ;
    END
  END tk[4]
  PIN tk[50]
    DIRECTION OUTPUT ;
    USE SIGNAL ;
    PORT
      LAYER M5 ;
        RECT  57.024 0 57.048 0.084 ;
    END
  END tk[50]
  PIN tk[51]
    DIRECTION OUTPUT ;
    USE SIGNAL ;
    PORT
      LAYER M5 ;
        RECT  38.736 0 38.76 0.084 ;
    END
  END tk[51]
  PIN tk[52]
    DIRECTION OUTPUT ;
    USE SIGNAL ;
    PORT
      LAYER M5 ;
        RECT  38.88 0 38.904 0.084 ;
    END
  END tk[52]
  PIN tk[53]
    DIRECTION OUTPUT ;
    USE SIGNAL ;
    PORT
      LAYER M5 ;
        RECT  39.024 0 39.048 0.084 ;
    END
  END tk[53]
  PIN tk[54]
    DIRECTION OUTPUT ;
    USE SIGNAL ;
    PORT
      LAYER M5 ;
        RECT  39.168 0 39.192 0.084 ;
    END
  END tk[54]
  PIN tk[55]
    DIRECTION OUTPUT ;
    USE SIGNAL ;
    PORT
      LAYER M5 ;
        RECT  39.312 0 39.336 0.084 ;
    END
  END tk[55]
  PIN tk[56]
    DIRECTION OUTPUT ;
    USE SIGNAL ;
    PORT
      LAYER M5 ;
        RECT  39.456 0 39.48 0.084 ;
    END
  END tk[56]
  PIN tk[57]
    DIRECTION OUTPUT ;
    USE SIGNAL ;
    PORT
      LAYER M5 ;
        RECT  39.6 0 39.624 0.084 ;
    END
  END tk[57]
  PIN tk[58]
    DIRECTION OUTPUT ;
    USE SIGNAL ;
    PORT
      LAYER M5 ;
        RECT  39.744 0 39.768 0.084 ;
    END
  END tk[58]
  PIN tk[59]
    DIRECTION OUTPUT ;
    USE SIGNAL ;
    PORT
      LAYER M5 ;
        RECT  39.888 0 39.912 0.084 ;
    END
  END tk[59]
  PIN tk[5]
    DIRECTION OUTPUT ;
    USE SIGNAL ;
    PORT
      LAYER M5 ;
        RECT  50.544 0 50.568 0.084 ;
    END
  END tk[5]
  PIN tk[60]
    DIRECTION OUTPUT ;
    USE SIGNAL ;
    PORT
      LAYER M5 ;
        RECT  40.032 0 40.056 0.084 ;
    END
  END tk[60]
  PIN tk[61]
    DIRECTION OUTPUT ;
    USE SIGNAL ;
    PORT
      LAYER M5 ;
        RECT  40.176 0 40.2 0.084 ;
    END
  END tk[61]
  PIN tk[62]
    DIRECTION OUTPUT ;
    USE SIGNAL ;
    PORT
      LAYER M5 ;
        RECT  40.32 0 40.344 0.084 ;
    END
  END tk[62]
  PIN tk[63]
    DIRECTION OUTPUT ;
    USE SIGNAL ;
    PORT
      LAYER M5 ;
        RECT  40.464 0 40.488 0.084 ;
    END
  END tk[63]
  PIN tk[64]
    DIRECTION OUTPUT ;
    USE SIGNAL ;
    PORT
      LAYER M5 ;
        RECT  40.608 0 40.632 0.084 ;
    END
  END tk[64]
  PIN tk[65]
    DIRECTION OUTPUT ;
    USE SIGNAL ;
    PORT
      LAYER M5 ;
        RECT  40.752 0 40.776 0.084 ;
    END
  END tk[65]
  PIN tk[66]
    DIRECTION OUTPUT ;
    USE SIGNAL ;
    PORT
      LAYER M5 ;
        RECT  40.896 0 40.92 0.084 ;
    END
  END tk[66]
  PIN tk[67]
    DIRECTION OUTPUT ;
    USE SIGNAL ;
    PORT
      LAYER M5 ;
        RECT  41.04 0 41.064 0.084 ;
    END
  END tk[67]
  PIN tk[68]
    DIRECTION OUTPUT ;
    USE SIGNAL ;
    PORT
      LAYER M5 ;
        RECT  41.184 0 41.208 0.084 ;
    END
  END tk[68]
  PIN tk[69]
    DIRECTION OUTPUT ;
    USE SIGNAL ;
    PORT
      LAYER M5 ;
        RECT  41.328 0 41.352 0.084 ;
    END
  END tk[69]
  PIN tk[6]
    DIRECTION OUTPUT ;
    USE SIGNAL ;
    PORT
      LAYER M5 ;
        RECT  50.688 0 50.712 0.084 ;
    END
  END tk[6]
  PIN tk[70]
    DIRECTION OUTPUT ;
    USE SIGNAL ;
    PORT
      LAYER M5 ;
        RECT  41.472 0 41.496 0.084 ;
    END
  END tk[70]
  PIN tk[71]
    DIRECTION OUTPUT ;
    USE SIGNAL ;
    PORT
      LAYER M5 ;
        RECT  41.616 0 41.64 0.084 ;
    END
  END tk[71]
  PIN tk[72]
    DIRECTION OUTPUT ;
    USE SIGNAL ;
    PORT
      LAYER M5 ;
        RECT  41.76 0 41.784 0.084 ;
    END
  END tk[72]
  PIN tk[73]
    DIRECTION OUTPUT ;
    USE SIGNAL ;
    PORT
      LAYER M5 ;
        RECT  41.904 0 41.928 0.084 ;
    END
  END tk[73]
  PIN tk[74]
    DIRECTION OUTPUT ;
    USE SIGNAL ;
    PORT
      LAYER M5 ;
        RECT  42.048 0 42.072 0.084 ;
    END
  END tk[74]
  PIN tk[75]
    DIRECTION OUTPUT ;
    USE SIGNAL ;
    PORT
      LAYER M5 ;
        RECT  42.192 0 42.216 0.084 ;
    END
  END tk[75]
  PIN tk[76]
    DIRECTION OUTPUT ;
    USE SIGNAL ;
    PORT
      LAYER M5 ;
        RECT  42.336 0 42.36 0.084 ;
    END
  END tk[76]
  PIN tk[77]
    DIRECTION OUTPUT ;
    USE SIGNAL ;
    PORT
      LAYER M5 ;
        RECT  42.48 0 42.504 0.084 ;
    END
  END tk[77]
  PIN tk[78]
    DIRECTION OUTPUT ;
    USE SIGNAL ;
    PORT
      LAYER M5 ;
        RECT  42.624 0 42.648 0.084 ;
    END
  END tk[78]
  PIN tk[79]
    DIRECTION OUTPUT ;
    USE SIGNAL ;
    PORT
      LAYER M5 ;
        RECT  42.768 0 42.792 0.084 ;
    END
  END tk[79]
  PIN tk[7]
    DIRECTION OUTPUT ;
    USE SIGNAL ;
    PORT
      LAYER M5 ;
        RECT  50.832 0 50.856 0.084 ;
    END
  END tk[7]
  PIN tk[80]
    DIRECTION OUTPUT ;
    USE SIGNAL ;
    PORT
      LAYER M5 ;
        RECT  42.912 0 42.936 0.084 ;
    END
  END tk[80]
  PIN tk[81]
    DIRECTION OUTPUT ;
    USE SIGNAL ;
    PORT
      LAYER M5 ;
        RECT  43.056 0 43.08 0.084 ;
    END
  END tk[81]
  PIN tk[82]
    DIRECTION OUTPUT ;
    USE SIGNAL ;
    PORT
      LAYER M5 ;
        RECT  43.2 0 43.224 0.084 ;
    END
  END tk[82]
  PIN tk[83]
    DIRECTION OUTPUT ;
    USE SIGNAL ;
    PORT
      LAYER M5 ;
        RECT  19.152 0 19.176 0.084 ;
    END
  END tk[83]
  PIN tk[84]
    DIRECTION OUTPUT ;
    USE SIGNAL ;
    PORT
      LAYER M5 ;
        RECT  19.296 0 19.32 0.084 ;
    END
  END tk[84]
  PIN tk[85]
    DIRECTION OUTPUT ;
    USE SIGNAL ;
    PORT
      LAYER M5 ;
        RECT  19.44 0 19.464 0.084 ;
    END
  END tk[85]
  PIN tk[86]
    DIRECTION OUTPUT ;
    USE SIGNAL ;
    PORT
      LAYER M5 ;
        RECT  19.584 0 19.608 0.084 ;
    END
  END tk[86]
  PIN tk[87]
    DIRECTION OUTPUT ;
    USE SIGNAL ;
    PORT
      LAYER M5 ;
        RECT  19.728 0 19.752 0.084 ;
    END
  END tk[87]
  PIN tk[88]
    DIRECTION OUTPUT ;
    USE SIGNAL ;
    PORT
      LAYER M5 ;
        RECT  19.872 0 19.896 0.084 ;
    END
  END tk[88]
  PIN tk[89]
    DIRECTION OUTPUT ;
    USE SIGNAL ;
    PORT
      LAYER M5 ;
        RECT  20.016 0 20.04 0.084 ;
    END
  END tk[89]
  PIN tk[8]
    DIRECTION OUTPUT ;
    USE SIGNAL ;
    PORT
      LAYER M5 ;
        RECT  50.976 0 51 0.084 ;
    END
  END tk[8]
  PIN tk[90]
    DIRECTION OUTPUT ;
    USE SIGNAL ;
    PORT
      LAYER M5 ;
        RECT  20.16 0 20.184 0.084 ;
    END
  END tk[90]
  PIN tk[91]
    DIRECTION OUTPUT ;
    USE SIGNAL ;
    PORT
      LAYER M5 ;
        RECT  20.304 0 20.328 0.084 ;
    END
  END tk[91]
  PIN tk[92]
    DIRECTION OUTPUT ;
    USE SIGNAL ;
    PORT
      LAYER M5 ;
        RECT  20.448 0 20.472 0.084 ;
    END
  END tk[92]
  PIN tk[9]
    DIRECTION OUTPUT ;
    USE SIGNAL ;
    PORT
      LAYER M5 ;
        RECT  51.12 0 51.144 0.084 ;
    END
  END tk[9]
  PIN x_cls[0]
    DIRECTION OUTPUT ;
    USE SIGNAL ;
    PORT
      LAYER M5 ;
        RECT  11.664 29.076 11.688 29.16 ;
    END
  END x_cls[0]
  PIN x_cls[1]
    DIRECTION OUTPUT ;
    USE SIGNAL ;
    PORT
      LAYER M5 ;
        RECT  11.808 29.076 11.832 29.16 ;
    END
  END x_cls[1]
  PIN x_cls[2]
    DIRECTION OUTPUT ;
    USE SIGNAL ;
    PORT
      LAYER M5 ;
        RECT  11.952 29.076 11.976 29.16 ;
    END
  END x_cls[2]
  PIN x_v
    DIRECTION OUTPUT ;
    USE SIGNAL ;
    PORT
      LAYER M5 ;
        RECT  12.096 29.076 12.12 29.16 ;
    END
  END x_v
  PIN VDD
    DIRECTION INOUT ;
    USE POWER ;
    PORT
      LAYER M5 ;
        RECT  61.992 2.151 62.112 27.009 ;
        RECT  59.292 2.151 59.412 27.009 ;
        RECT  56.592 2.151 56.712 27.009 ;
        RECT  53.892 2.151 54.012 27.009 ;
        RECT  51.192 2.151 51.312 27.009 ;
        RECT  48.492 2.151 48.612 27.009 ;
        RECT  45.792 2.151 45.912 27.009 ;
        RECT  43.092 2.151 43.212 27.009 ;
        RECT  40.392 2.151 40.512 27.009 ;
        RECT  37.692 2.151 37.812 27.009 ;
        RECT  34.992 2.151 35.112 27.009 ;
        RECT  32.292 2.151 32.412 27.009 ;
        RECT  29.592 2.151 29.712 27.009 ;
        RECT  26.892 2.151 27.012 27.009 ;
        RECT  24.192 2.151 24.312 27.009 ;
        RECT  21.492 2.151 21.612 27.009 ;
        RECT  18.792 2.151 18.912 27.009 ;
        RECT  16.092 2.151 16.212 27.009 ;
        RECT  13.392 2.151 13.512 27.009 ;
        RECT  10.692 2.151 10.812 27.009 ;
        RECT  7.992 2.151 8.112 27.009 ;
        RECT  5.292 2.151 5.412 27.009 ;
        RECT  2.592 2.151 2.712 27.009 ;
    END
  END VDD
  PIN VSS
    DIRECTION INOUT ;
    USE GROUND ;
    PORT
      LAYER M5 ;
        RECT  61.8 2.137 61.92 27.023 ;
        RECT  59.1 2.137 59.22 27.023 ;
        RECT  56.4 2.137 56.52 27.023 ;
        RECT  53.7 2.137 53.82 27.023 ;
        RECT  51 2.137 51.12 27.023 ;
        RECT  48.3 2.137 48.42 27.023 ;
        RECT  45.6 2.137 45.72 27.023 ;
        RECT  42.9 2.137 43.02 27.023 ;
        RECT  40.2 2.137 40.32 27.023 ;
        RECT  37.5 2.137 37.62 27.023 ;
        RECT  34.8 2.137 34.92 27.023 ;
        RECT  32.1 2.137 32.22 27.023 ;
        RECT  29.4 2.137 29.52 27.023 ;
        RECT  26.7 2.137 26.82 27.023 ;
        RECT  24 2.137 24.12 27.023 ;
        RECT  21.3 2.137 21.42 27.023 ;
        RECT  18.6 2.137 18.72 27.023 ;
        RECT  15.9 2.137 16.02 27.023 ;
        RECT  13.2 2.137 13.32 27.023 ;
        RECT  10.5 2.137 10.62 27.023 ;
        RECT  7.8 2.137 7.92 27.023 ;
        RECT  5.1 2.137 5.22 27.023 ;
        RECT  2.4 2.137 2.52 27.023 ;
    END
  END VSS
  OBS
    LAYER RVTN ;
     RECT  2.16 2.16 62.64 2.295 ;
     RECT  2.16 2.565 62.64 2.835 ;
     RECT  2.16 3.105 62.64 3.375 ;
     RECT  2.16 3.645 62.64 3.915 ;
     RECT  2.16 4.185 62.64 4.455 ;
     RECT  2.16 4.725 62.64 4.995 ;
     RECT  2.16 5.265 62.64 5.535 ;
     RECT  2.16 5.805 62.64 6.075 ;
     RECT  2.16 6.345 62.64 6.615 ;
     RECT  2.16 6.885 62.64 7.155 ;
     RECT  2.16 7.425 62.64 7.695 ;
     RECT  2.16 7.965 62.64 8.235 ;
     RECT  2.16 8.505 62.64 8.775 ;
     RECT  2.16 9.045 62.64 9.315 ;
     RECT  2.16 9.585 62.64 9.855 ;
     RECT  2.16 10.125 62.64 10.395 ;
     RECT  2.16 10.665 62.64 10.935 ;
     RECT  2.16 11.205 62.64 11.475 ;
     RECT  2.16 11.745 62.64 12.015 ;
     RECT  2.16 12.285 62.64 12.555 ;
     RECT  2.16 12.825 62.64 13.095 ;
     RECT  2.16 13.365 62.64 13.635 ;
     RECT  2.16 13.905 62.64 14.175 ;
     RECT  2.16 14.445 62.64 14.715 ;
     RECT  2.16 14.985 62.64 15.255 ;
     RECT  2.16 15.525 62.64 15.795 ;
     RECT  2.16 16.065 62.64 16.335 ;
     RECT  2.16 16.605 62.64 16.875 ;
     RECT  2.16 17.145 62.64 17.415 ;
     RECT  2.16 17.685 62.64 17.955 ;
     RECT  2.16 18.225 62.64 18.495 ;
     RECT  2.16 18.765 62.64 19.035 ;
     RECT  2.16 19.305 62.64 19.575 ;
     RECT  2.16 19.845 62.64 20.115 ;
     RECT  2.16 20.385 62.64 20.655 ;
     RECT  2.16 20.925 62.64 21.195 ;
     RECT  2.16 21.465 62.64 21.735 ;
     RECT  2.16 22.005 62.64 22.275 ;
     RECT  2.16 22.545 62.64 22.815 ;
     RECT  2.16 23.085 62.64 23.355 ;
     RECT  2.16 23.625 62.64 23.895 ;
     RECT  2.16 24.165 62.64 24.435 ;
     RECT  2.16 24.705 62.64 24.975 ;
     RECT  2.16 25.245 62.64 25.515 ;
     RECT  2.16 25.785 62.64 26.055 ;
     RECT  2.16 26.325 62.64 26.595 ;
     RECT  2.16 26.865 62.64 27 ;
    LAYER RVTP ;
     RECT  2.16 2.295 62.64 2.565 ;
     RECT  2.16 2.835 62.64 3.105 ;
     RECT  2.16 3.375 62.64 3.645 ;
     RECT  2.16 3.915 62.64 4.185 ;
     RECT  2.16 4.455 62.64 4.725 ;
     RECT  2.16 4.995 62.64 5.265 ;
     RECT  2.16 5.535 62.64 5.805 ;
     RECT  2.16 6.075 62.64 6.345 ;
     RECT  2.16 6.615 62.64 6.885 ;
     RECT  2.16 7.155 62.64 7.425 ;
     RECT  2.16 7.695 62.64 7.965 ;
     RECT  2.16 8.235 62.64 8.505 ;
     RECT  2.16 8.775 62.64 9.045 ;
     RECT  2.16 9.315 62.64 9.585 ;
     RECT  2.16 9.855 62.64 10.125 ;
     RECT  2.16 10.395 62.64 10.665 ;
     RECT  2.16 10.935 62.64 11.205 ;
     RECT  2.16 11.475 62.64 11.745 ;
     RECT  2.16 12.015 62.64 12.285 ;
     RECT  2.16 12.555 62.64 12.825 ;
     RECT  2.16 13.095 62.64 13.365 ;
     RECT  2.16 13.635 62.64 13.905 ;
     RECT  2.16 14.175 62.64 14.445 ;
     RECT  2.16 14.715 62.64 14.985 ;
     RECT  2.16 15.255 62.64 15.525 ;
     RECT  2.16 15.795 62.64 16.065 ;
     RECT  2.16 16.335 62.64 16.605 ;
     RECT  2.16 16.875 62.64 17.145 ;
     RECT  2.16 17.415 62.64 17.685 ;
     RECT  2.16 17.955 62.64 18.225 ;
     RECT  2.16 18.495 62.64 18.765 ;
     RECT  2.16 19.035 62.64 19.305 ;
     RECT  2.16 19.575 62.64 19.845 ;
     RECT  2.16 20.115 62.64 20.385 ;
     RECT  2.16 20.655 62.64 20.925 ;
     RECT  2.16 21.195 62.64 21.465 ;
     RECT  2.16 21.735 62.64 22.005 ;
     RECT  2.16 22.275 62.64 22.545 ;
     RECT  2.16 22.815 62.64 23.085 ;
     RECT  2.16 23.355 62.64 23.625 ;
     RECT  2.16 23.895 62.64 24.165 ;
     RECT  2.16 24.435 62.64 24.705 ;
     RECT  2.16 24.975 62.64 25.245 ;
     RECT  2.16 25.515 62.64 25.785 ;
     RECT  2.16 26.055 62.64 26.325 ;
     RECT  2.16 26.595 62.64 26.865 ;
    LAYER M1 ;
     RECT  2.16 2.151 62.64 27.009 ;
    LAYER M2 ;
     RECT  0.103 10.944 0.139 10.962 ;
     RECT  0.067 3.501 0.167 3.519 ;
     RECT  0.103 9.63 0.535 9.648 ;
     RECT  0.139 10.746 0.535 10.962 ;
     RECT  0.103 5.076 1.723 5.094 ;
     RECT  0.103 14.22 1.759 14.238 ;
     RECT  1.759 14.22 1.975 14.544 ;
     RECT  1.939 15.534 1.975 15.552 ;
     RECT  0.535 2.916 2.16 2.934 ;
     RECT  1.723 5.076 2.16 5.562 ;
     RECT  0.103 6.696 2.16 6.714 ;
     RECT  0.067 7.506 2.16 7.524 ;
     RECT  0.535 9.054 2.16 9.648 ;
     RECT  0.535 10.746 2.16 11.232 ;
     RECT  1.975 14.22 2.16 15.552 ;
     RECT  2.16 2.151 3.055 27.009 ;
     RECT  3.055 2.106 4.279 27.009 ;
     RECT  4.279 2.034 5.071 27.009 ;
     RECT  5.071 1.962 8.735 27.009 ;
     RECT  8.735 2.106 9.203 27.009 ;
     RECT  9.203 2.151 12.091 27.009 ;
     RECT  12.091 2.106 14.971 27.009 ;
     RECT  14.971 2.07 15.827 27.009 ;
     RECT  15.827 2.106 16.555 27.009 ;
     RECT  16.051 1.152 17.195 1.17 ;
     RECT  16.555 2.07 17.735 27.009 ;
     RECT  17.735 2.106 22.703 27.009 ;
     RECT  22.703 2.151 29.875 27.009 ;
     RECT  29.875 2.106 31.883 27.009 ;
     RECT  31.883 2.151 37.903 27.009 ;
     RECT  37.903 2.106 38.903 27.009 ;
     RECT  41.035 1.152 41.279 1.17 ;
     RECT  43.231 1.152 43.331 1.17 ;
     RECT  38.903 2.151 43.771 27.009 ;
     RECT  43.771 2.106 45.599 27.009 ;
     RECT  45.599 2.151 46.759 27.009 ;
     RECT  46.759 2.106 51.863 27.009 ;
     RECT  51.863 2.151 53.851 27.009 ;
     RECT  53.851 2.106 54.995 27.009 ;
     RECT  55.147 1.152 56.183 1.17 ;
     RECT  54.995 2.151 56.947 27.009 ;
     RECT  57.343 1.152 57.551 1.17 ;
     RECT  58.279 1.152 58.379 1.17 ;
     RECT  56.947 2.106 62.447 27.009 ;
     RECT  62.447 2.151 62.64 27.009 ;
     RECT  62.64 4.122 62.663 7.074 ;
     RECT  62.64 7.938 63.239 15.318 ;
     RECT  62.64 16.146 63.275 18.954 ;
     RECT  62.663 4.266 63.851 7.074 ;
     RECT  63.239 8.136 63.851 15.174 ;
     RECT  63.275 17.856 63.851 18.864 ;
     RECT  63.851 8.586 63.887 8.604 ;
     RECT  63.851 11.826 63.887 15.084 ;
     RECT  63.851 4.266 63.923 5.904 ;
     RECT  63.923 5.274 63.959 5.904 ;
     RECT  63.923 4.266 63.995 4.284 ;
     RECT  63.851 9.558 63.995 10.998 ;
     RECT  63.995 9.558 64.535 10.458 ;
     RECT  64.535 9.558 64.607 10.422 ;
     RECT  64.607 9.558 64.643 10.269 ;
     RECT  63.887 12.906 64.643 13.932 ;
     RECT  63.275 16.146 64.643 16.938 ;
     RECT  63.851 18.234 64.643 18.864 ;
     RECT  63.851 6.696 64.679 6.714 ;
     RECT  64.643 9.594 64.679 10.269 ;
     RECT  63.887 11.826 64.679 12.006 ;
     RECT  64.643 12.906 64.679 13.734 ;
     RECT  63.887 14.796 64.679 15.084 ;
     RECT  64.643 16.344 64.679 16.938 ;
     RECT  64.643 18.234 64.679 18.324 ;
     RECT  63.959 5.886 64.715 5.904 ;
     RECT  64.679 9.594 64.715 9.612 ;
     RECT  64.679 11.826 64.715 11.844 ;
     RECT  64.679 13.446 64.715 13.734 ;
     RECT  64.679 15.066 64.715 15.084 ;
     RECT  64.679 16.92 64.715 16.938 ;
     RECT  64.679 18.306 64.715 18.324 ;
    LAYER M3 ;
     RECT  54.9 0.091 55.206 0.139 ;
     RECT  56.16 0.091 56.862 0.139 ;
     RECT  38.448 0.091 39.186 0.187 ;
     RECT  62.208 0.091 62.514 0.187 ;
     RECT  49.248 0.091 49.266 0.235 ;
     RECT  16.488 0.091 17.838 0.475 ;
     RECT  49.176 0.235 49.266 0.475 ;
     RECT  50.328 0.091 50.346 0.475 ;
     RECT  56.16 0.139 56.934 0.475 ;
     RECT  58.212 0.187 58.23 0.475 ;
     RECT  51.444 0.091 52.254 0.523 ;
     RECT  54.756 0.139 55.206 0.523 ;
     RECT  56.16 0.475 58.23 0.523 ;
     RECT  38.412 0.187 39.186 0.571 ;
     RECT  39.924 0.091 39.942 0.571 ;
     RECT  51.444 0.523 52.722 0.571 ;
     RECT  38.412 0.571 39.942 1.099 ;
     RECT  41.04 0.091 41.058 1.099 ;
     RECT  14.544 0.571 14.562 1.147 ;
     RECT  38.412 1.099 41.058 1.147 ;
     RECT  43.308 0.091 43.326 1.147 ;
     RECT  51.444 0.571 52.866 1.147 ;
     RECT  54.072 0.523 55.278 1.147 ;
     RECT  56.16 0.523 58.302 1.147 ;
     RECT  59.688 0.091 59.706 1.147 ;
     RECT  51.444 1.147 58.374 1.175 ;
     RECT  7.128 1.291 7.146 1.435 ;
     RECT  7.128 1.435 7.254 1.579 ;
     RECT  38.412 1.147 41.49 1.627 ;
     RECT  49.176 0.475 50.346 1.627 ;
     RECT  49.176 1.627 50.418 1.675 ;
     RECT  8.856 1.147 8.874 1.723 ;
     RECT  14.544 1.147 14.85 1.723 ;
     RECT  15.768 0.475 17.838 1.723 ;
     RECT  38.412 1.627 42.102 1.723 ;
     RECT  43.236 1.147 43.326 1.723 ;
     RECT  44.064 0.139 44.082 1.723 ;
     RECT  46.404 0.091 46.89 1.723 ;
     RECT  48.456 1.675 50.418 1.723 ;
     RECT  51.444 1.175 55.89 1.723 ;
     RECT  56.844 1.175 58.374 1.723 ;
     RECT  59.616 1.147 59.706 1.723 ;
     RECT  61.164 1.771 61.326 1.819 ;
     RECT  7.128 1.579 7.506 1.915 ;
     RECT  5.076 1.957 5.094 1.993 ;
     RECT  6.984 1.915 7.506 1.993 ;
     RECT  8.64 1.723 8.874 2.011 ;
     RECT  56.844 1.723 60.21 2.011 ;
     RECT  61.164 1.819 61.434 2.011 ;
     RECT  62.172 0.187 62.514 2.011 ;
     RECT  3.888 1.003 3.906 2.029 ;
     RECT  0.108 0.859 0.126 2.059 ;
     RECT  38.412 1.723 44.658 2.059 ;
     RECT  56.772 2.011 60.21 2.059 ;
     RECT  61.164 2.011 62.514 2.059 ;
     RECT  2.592 2.059 2.862 2.101 ;
     RECT  5.076 1.993 5.814 2.101 ;
     RECT  6.552 1.993 7.506 2.101 ;
     RECT  8.352 2.011 8.874 2.101 ;
     RECT  22.284 0.091 22.302 2.101 ;
     RECT  29.592 2.059 29.61 2.101 ;
     RECT  2.592 2.101 3.078 2.143 ;
     RECT  21.564 2.101 22.698 2.143 ;
     RECT  29.592 2.101 29.898 2.143 ;
     RECT  31.86 2.101 31.878 2.143 ;
     RECT  37.692 2.059 44.658 2.143 ;
     RECT  45.432 1.723 55.89 2.143 ;
     RECT  56.772 2.059 62.514 2.143 ;
     RECT  0.108 2.059 0.162 2.189 ;
     RECT  2.415 2.143 3.078 2.191 ;
     RECT  3.888 2.029 4.302 2.191 ;
     RECT  5.076 2.101 9.198 2.191 ;
     RECT  14.544 1.723 20.466 2.191 ;
     RECT  21.315 2.143 22.698 2.191 ;
     RECT  24.015 2.143 24.105 2.191 ;
     RECT  30.78 2.059 30.798 2.191 ;
     RECT  37.515 2.143 44.658 2.191 ;
     RECT  45.432 2.143 62.514 2.191 ;
     RECT  2.415 2.191 9.198 2.219 ;
     RECT  37.152 2.191 62.514 2.227 ;
     RECT  25.344 2.191 25.362 2.263 ;
     RECT  24.015 2.191 24.426 2.293 ;
     RECT  25.344 2.263 25.578 2.293 ;
     RECT  14.544 2.191 22.95 2.299 ;
     RECT  23.94 2.293 25.578 2.299 ;
     RECT  26.676 2.059 26.874 2.299 ;
     RECT  29.415 2.143 29.898 2.299 ;
     RECT  30.636 2.191 30.798 2.299 ;
     RECT  31.86 2.143 32.205 2.299 ;
     RECT  13.215 2.143 13.305 2.335 ;
     RECT  2.415 2.219 8.874 2.371 ;
     RECT  34.815 2.143 34.905 2.371 ;
     RECT  37.08 2.227 62.514 2.371 ;
     RECT  10.515 2.143 10.605 2.413 ;
     RECT  29.415 2.299 32.205 2.413 ;
     RECT  34.776 2.371 34.905 2.413 ;
     RECT  36.216 2.227 36.234 2.443 ;
     RECT  13.215 2.335 13.77 2.461 ;
     RECT  14.544 2.299 25.578 2.461 ;
     RECT  26.676 2.299 27.09 2.461 ;
     RECT  29.415 2.413 32.397 2.461 ;
     RECT  2.304 2.371 8.874 2.489 ;
     RECT  26.496 2.461 27.09 2.497 ;
     RECT  28.08 2.299 28.098 2.497 ;
     RECT  28.944 2.461 32.397 2.497 ;
     RECT  33.732 2.335 33.75 2.497 ;
     RECT  34.776 2.413 35.097 2.497 ;
     RECT  13.215 2.461 25.578 2.533 ;
     RECT  26.352 2.497 32.598 2.533 ;
     RECT  33.732 2.497 35.097 2.569 ;
     RECT  37.08 2.371 62.55 2.569 ;
     RECT  13.215 2.533 32.598 2.641 ;
     RECT  33.444 2.569 35.097 2.641 ;
     RECT  35.892 2.443 36.234 2.641 ;
     RECT  37.008 2.569 62.55 2.641 ;
     RECT  2.304 2.489 8.73 2.669 ;
     RECT  35.892 2.641 62.55 2.669 ;
     RECT  13.215 2.641 35.097 2.731 ;
     RECT  36.036 2.669 62.55 2.831 ;
     RECT  0.108 2.189 0.126 2.911 ;
     RECT  10.515 2.413 10.797 3.271 ;
     RECT  12.096 2.101 12.114 3.271 ;
     RECT  10.515 3.271 12.114 3.307 ;
     RECT  13.104 2.731 35.097 3.307 ;
     RECT  2.304 2.669 8.658 3.403 ;
     RECT  0.108 2.911 0.558 3.496 ;
     RECT  0.072 3.496 0.558 3.629 ;
     RECT  10.515 3.307 35.097 3.685 ;
     RECT  36.18 2.831 62.55 3.721 ;
     RECT  0.072 3.629 0.162 3.869 ;
     RECT  36.108 3.721 62.55 3.979 ;
     RECT  36.108 3.979 62.658 4.145 ;
     RECT  2.304 3.403 9.162 4.253 ;
     RECT  2.304 4.253 8.586 4.315 ;
     RECT  10.515 3.685 35.37 4.351 ;
     RECT  36.108 4.145 62.55 4.351 ;
     RECT  2.268 4.315 8.586 4.459 ;
     RECT  10.515 4.351 62.55 4.559 ;
     RECT  0.072 3.869 0.126 4.603 ;
     RECT  63.972 4.261 63.99 4.621 ;
     RECT  26.208 4.559 62.55 4.649 ;
     RECT  26.424 4.649 62.55 4.757 ;
     RECT  10.515 4.559 25.47 4.801 ;
     RECT  9.396 4.693 9.414 4.919 ;
     RECT  26.424 4.757 62.514 4.919 ;
     RECT  1.728 4.459 8.586 4.955 ;
     RECT  10.296 4.801 25.47 5.035 ;
     RECT  63.864 4.621 63.99 5.341 ;
     RECT  26.424 4.919 62.442 5.431 ;
     RECT  10.188 5.035 25.47 5.467 ;
     RECT  63.828 5.341 63.99 5.515 ;
     RECT  1.728 4.955 8.406 5.567 ;
     RECT  10.188 5.467 25.65 5.611 ;
     RECT  26.388 5.431 62.442 5.611 ;
     RECT  9.18 5.431 9.198 5.701 ;
     RECT  10.188 5.611 62.442 5.701 ;
     RECT  2.304 5.567 8.406 5.737 ;
     RECT  9.18 5.701 62.442 5.737 ;
     RECT  2.304 5.737 62.442 5.873 ;
     RECT  63.828 5.515 64.638 5.881 ;
     RECT  9.396 5.873 62.442 5.899 ;
     RECT  9.396 5.899 62.874 6.029 ;
     RECT  63.828 5.881 64.71 6.509 ;
     RECT  0.072 4.603 0.162 6.605 ;
     RECT  2.304 5.873 8.478 6.667 ;
     RECT  2.124 6.667 8.478 6.691 ;
     RECT  9.396 6.029 62.478 6.691 ;
     RECT  2.124 6.691 62.478 6.797 ;
     RECT  63.828 6.509 63.918 7.079 ;
     RECT  63.9 7.079 63.918 7.085 ;
     RECT  2.304 6.797 62.478 7.373 ;
     RECT  64.656 6.509 64.71 7.373 ;
     RECT  6.84 7.373 62.478 7.393 ;
     RECT  64.656 7.373 64.674 7.517 ;
     RECT  0.072 6.605 0.126 7.529 ;
     RECT  2.304 7.373 6.066 7.619 ;
     RECT  0.108 7.529 0.126 7.771 ;
     RECT  2.304 7.619 6.03 7.889 ;
     RECT  6.84 7.393 62.514 7.889 ;
     RECT  20.268 7.889 62.514 7.933 ;
     RECT  63.252 7.819 63.27 7.933 ;
     RECT  0.108 7.771 0.342 7.949 ;
     RECT  64.512 7.771 64.53 7.949 ;
     RECT  20.268 7.933 63.27 8.059 ;
     RECT  6.84 7.889 19.458 8.131 ;
     RECT  6.804 8.131 19.458 8.401 ;
     RECT  6.696 8.401 19.458 8.671 ;
     RECT  20.268 8.059 63.882 8.671 ;
     RECT  6.696 8.671 63.882 8.735 ;
     RECT  2.304 7.889 5.958 8.851 ;
     RECT  6.696 8.735 41.454 8.851 ;
     RECT  64.692 8.635 64.71 8.923 ;
     RECT  42.192 8.735 63.882 9.041 ;
     RECT  0.144 7.949 0.162 9.049 ;
     RECT  64.656 8.923 64.71 9.211 ;
     RECT  63.144 9.041 63.882 9.499 ;
     RECT  64.62 9.211 64.71 9.499 ;
     RECT  63.144 9.499 64.71 9.617 ;
     RECT  0.144 9.049 0.558 9.625 ;
     RECT  0.108 9.625 0.558 9.677 ;
     RECT  0.108 9.677 0.126 9.821 ;
     RECT  2.304 8.851 41.454 9.883 ;
     RECT  42.192 9.041 62.226 9.883 ;
     RECT  2.304 9.883 62.226 9.931 ;
     RECT  63.144 9.617 64.674 9.931 ;
     RECT  2.304 9.931 64.674 10.705 ;
     RECT  0.144 10.741 0.162 10.939 ;
     RECT  0.108 10.939 0.162 11.209 ;
     RECT  2.232 10.705 64.674 11.471 ;
     RECT  2.268 11.471 64.674 11.501 ;
     RECT  0.108 11.209 0.558 11.549 ;
     RECT  2.268 11.501 63.918 11.669 ;
     RECT  0.144 11.549 0.558 11.693 ;
     RECT  64.656 11.501 64.674 11.803 ;
     RECT  0.144 11.693 0.342 11.837 ;
     RECT  2.304 11.669 63.918 11.981 ;
     RECT  63.288 11.981 63.918 12.125 ;
     RECT  0.324 11.837 0.342 12.269 ;
     RECT  64.656 11.803 64.71 12.667 ;
     RECT  2.304 11.981 62.514 12.811 ;
     RECT  63.288 12.125 63.882 12.811 ;
     RECT  2.304 12.811 63.882 12.989 ;
     RECT  63.828 12.989 63.882 13.019 ;
     RECT  2.304 12.989 62.694 13.387 ;
     RECT  63.864 13.019 63.882 13.421 ;
     RECT  64.62 12.667 64.71 13.739 ;
     RECT  64.62 13.739 64.674 13.937 ;
     RECT  0.144 13.531 0.162 13.963 ;
     RECT  1.764 13.387 62.694 13.963 ;
     RECT  1.764 13.963 63.27 13.973 ;
     RECT  0.144 13.963 0.342 14.141 ;
     RECT  44.748 13.973 63.27 14.215 ;
     RECT  44.748 14.215 63.882 14.285 ;
     RECT  0.108 14.215 0.126 14.429 ;
     RECT  64.656 13.937 64.674 14.539 ;
     RECT  1.764 13.973 43.938 14.549 ;
     RECT  1.944 14.549 43.938 14.639 ;
     RECT  6.228 14.639 43.938 14.755 ;
     RECT  6.228 14.755 44.01 14.783 ;
     RECT  64.656 14.539 64.71 14.819 ;
     RECT  7.38 14.783 44.01 14.923 ;
     RECT  44.748 14.285 63.846 14.923 ;
     RECT  1.944 14.639 5.454 14.957 ;
     RECT  6.228 14.783 6.606 14.981 ;
     RECT  7.38 14.923 63.846 15.089 ;
     RECT  7.452 15.089 63.846 15.149 ;
     RECT  7.452 15.149 62.298 15.179 ;
     RECT  63.18 15.149 63.846 15.179 ;
     RECT  1.944 14.957 5.397 15.287 ;
     RECT  7.776 15.179 62.298 15.293 ;
     RECT  4.608 15.287 5.397 15.449 ;
     RECT  7.776 15.293 55.278 15.485 ;
     RECT  1.944 15.287 3.762 15.557 ;
     RECT  2.415 15.557 3.762 15.719 ;
     RECT  2.415 15.719 3.222 15.755 ;
     RECT  6.588 14.981 6.606 15.791 ;
     RECT  64.692 14.819 64.71 15.835 ;
     RECT  7.776 15.485 55.062 15.961 ;
     RECT  56.088 15.293 62.298 15.961 ;
     RECT  64.656 15.835 64.71 15.979 ;
     RECT  7.236 15.961 55.062 16.013 ;
     RECT  63.18 15.179 63.81 16.123 ;
     RECT  64.62 15.979 64.71 16.169 ;
     RECT  56.088 15.961 62.334 16.267 ;
     RECT  64.656 16.169 64.71 16.367 ;
     RECT  7.38 16.013 55.062 16.439 ;
     RECT  7.776 16.439 55.062 16.645 ;
     RECT  55.98 16.267 62.334 16.645 ;
     RECT  63.18 16.123 63.846 16.907 ;
     RECT  7.776 16.645 62.334 16.979 ;
     RECT  63.216 16.907 63.846 16.979 ;
     RECT  64.692 16.367 64.71 17.131 ;
     RECT  64.656 17.131 64.71 17.419 ;
     RECT  7.776 16.979 59.397 17.609 ;
     RECT  57.42 17.609 59.397 17.645 ;
     RECT  7.776 17.609 56.697 17.879 ;
     RECT  57.564 17.645 59.397 17.879 ;
     RECT  63.252 16.979 63.846 17.879 ;
     RECT  7.776 17.879 51.75 17.987 ;
     RECT  52.524 17.879 56.697 17.987 ;
     RECT  60.12 16.979 62.334 17.989 ;
     RECT  63.252 17.879 63.81 17.989 ;
     RECT  7.776 17.987 51.642 18.023 ;
     RECT  52.524 17.987 55.242 18.023 ;
     RECT  60.12 17.989 63.81 18.029 ;
     RECT  57.636 17.879 59.397 18.031 ;
     RECT  60.12 18.029 62.262 18.031 ;
     RECT  7.776 18.023 50.202 18.139 ;
     RECT  64.62 17.419 64.71 18.139 ;
     RECT  7.488 18.139 50.202 18.149 ;
     RECT  52.524 18.023 54.738 18.149 ;
     RECT  56.052 17.987 56.697 18.149 ;
     RECT  63.252 18.029 63.81 18.149 ;
     RECT  7.488 18.149 48.597 18.185 ;
     RECT  49.356 18.149 49.374 18.185 ;
     RECT  52.524 18.149 53.997 18.185 ;
     RECT  50.184 18.149 50.202 18.221 ;
     RECT  53.064 18.185 53.997 18.221 ;
     RECT  54.72 18.149 54.738 18.221 ;
     RECT  57.636 18.031 62.262 18.227 ;
     RECT  57.96 18.227 62.262 18.269 ;
     RECT  64.584 18.139 64.71 18.329 ;
     RECT  7.488 18.185 44.298 18.419 ;
     RECT  7.488 18.419 24.426 18.427 ;
     RECT  58.14 18.269 62.262 18.455 ;
     RECT  6.804 18.427 24.426 18.499 ;
     RECT  6.408 18.499 24.426 18.535 ;
     RECT  6.336 18.535 24.426 18.563 ;
     RECT  64.584 18.329 64.638 18.563 ;
     RECT  58.752 18.455 60.246 18.599 ;
     RECT  63.252 18.149 63.774 18.599 ;
     RECT  63.252 18.599 63.738 18.689 ;
     RECT  61.056 18.455 62.262 18.805 ;
     RECT  61.056 18.805 62.298 18.841 ;
     RECT  64.62 18.563 64.638 18.869 ;
     RECT  59.115 18.599 60.246 18.959 ;
     RECT  61.056 18.841 62.37 18.959 ;
     RECT  63.252 18.689 63.27 18.959 ;
     RECT  25.416 18.419 44.298 19.075 ;
     RECT  45.036 18.185 48.597 19.075 ;
     RECT  59.115 18.959 60.066 19.229 ;
     RECT  61.056 18.959 62.298 19.229 ;
     RECT  25.416 19.075 48.597 19.265 ;
     RECT  61.596 19.229 62.097 19.265 ;
     RECT  6.336 18.563 13.77 19.301 ;
     RECT  25.416 19.265 39.258 19.309 ;
     RECT  39.996 19.265 48.597 19.373 ;
     RECT  14.688 18.563 24.426 19.507 ;
     RECT  14.688 19.507 24.534 19.607 ;
     RECT  12.6 19.301 13.77 19.615 ;
     RECT  5.115 15.449 5.397 19.651 ;
     RECT  6.336 19.301 11.862 19.651 ;
     RECT  14.904 19.607 24.534 19.651 ;
     RECT  25.308 19.309 39.258 19.651 ;
     RECT  12.6 19.615 14.094 19.661 ;
     RECT  12.6 19.661 13.806 19.805 ;
     RECT  14.904 19.651 39.258 19.841 ;
     RECT  17.1 19.841 39.258 19.913 ;
     RECT  12.6 19.805 13.77 20.075 ;
     RECT  5.115 19.651 11.862 20.183 ;
     RECT  12.78 20.075 13.77 20.183 ;
     RECT  33.696 19.913 39.258 20.191 ;
     RECT  40.032 19.373 48.597 20.191 ;
     RECT  5.115 20.183 11.754 20.219 ;
     RECT  5.115 20.219 8.298 20.345 ;
     RECT  6.516 20.345 8.298 20.615 ;
     RECT  6.552 20.615 8.298 20.687 ;
     RECT  12.852 20.183 13.77 20.695 ;
     RECT  14.904 19.841 16.326 20.695 ;
     RECT  6.66 20.687 8.298 20.723 ;
     RECT  17.1 19.913 32.958 20.731 ;
     RECT  33.696 20.191 48.597 20.731 ;
     RECT  12.852 20.695 16.326 20.857 ;
     RECT  17.1 20.731 48.597 20.857 ;
     RECT  7.416 20.723 8.298 21.001 ;
     RECT  9.108 20.219 11.754 21.001 ;
     RECT  7.416 21.001 11.754 21.091 ;
     RECT  12.852 20.857 48.597 21.091 ;
     RECT  7.416 21.091 48.597 21.505 ;
     RECT  7.38 21.505 48.597 21.541 ;
     RECT  6.732 21.541 48.597 21.811 ;
     RECT  6.588 21.811 48.597 21.869 ;
     RECT  6.912 21.869 48.597 22.379 ;
     RECT  6.912 22.379 40.554 22.541 ;
     RECT  6.912 22.541 40.497 22.781 ;
     RECT  7.092 22.781 40.497 23.431 ;
     RECT  41.292 22.379 48.597 23.431 ;
     RECT  6.192 23.371 6.354 23.549 ;
     RECT  7.092 23.431 48.597 23.557 ;
     RECT  6.192 23.549 6.21 23.585 ;
     RECT  7.056 23.557 48.597 23.855 ;
     RECT  7.164 23.855 48.597 24.233 ;
     RECT  25.632 24.233 48.597 24.503 ;
     RECT  25.632 24.503 46.674 24.557 ;
     RECT  47.592 24.503 48.597 24.701 ;
     RECT  28.584 24.557 46.674 24.773 ;
     RECT  28.584 24.773 46.386 24.899 ;
     RECT  28.584 24.899 46.314 24.971 ;
     RECT  7.164 24.233 24.858 25.003 ;
     RECT  7.056 25.003 24.858 25.007 ;
     RECT  7.815 25.007 24.858 25.015 ;
     RECT  25.632 24.557 27.666 25.015 ;
     RECT  7.056 25.007 7.074 25.043 ;
     RECT  7.815 25.015 27.666 25.169 ;
     RECT  28.872 24.971 46.314 25.169 ;
     RECT  7.815 25.169 8.478 25.205 ;
     RECT  28.872 25.169 46.134 25.241 ;
     RECT  9.252 25.169 27.666 25.321 ;
     RECT  28.872 25.241 45.897 25.325 ;
     RECT  28.872 25.325 43.326 25.439 ;
     RECT  44.064 25.325 45.897 25.439 ;
     RECT  9.252 25.321 28.134 25.475 ;
     RECT  31.284 25.439 43.326 25.583 ;
     RECT  44.064 25.439 44.082 25.583 ;
     RECT  44.892 25.439 45.897 25.583 ;
     RECT  25.164 25.475 26.997 25.619 ;
     RECT  31.392 25.583 43.326 25.619 ;
     RECT  25.164 25.619 25.866 25.709 ;
     RECT  31.392 25.619 43.254 25.709 ;
     RECT  31.392 25.709 32.397 25.745 ;
     RECT  28.872 25.439 30.51 25.805 ;
     RECT  27.936 25.475 28.134 25.861 ;
     RECT  28.872 25.805 29.79 25.861 ;
     RECT  27.936 25.861 29.79 25.889 ;
     RECT  9.9 25.475 24.297 25.979 ;
     RECT  27.936 25.889 29.697 25.979 ;
     RECT  32.004 25.745 32.397 25.979 ;
     RECT  25.164 25.709 25.686 26.015 ;
     RECT  27.936 25.979 28.278 26.015 ;
     RECT  29.052 25.979 29.697 26.015 ;
     RECT  33.156 25.709 43.197 26.015 ;
     RECT  28.26 26.015 28.278 26.159 ;
     RECT  10.296 25.979 24.297 26.203 ;
     RECT  10.296 26.203 24.894 26.249 ;
     RECT  33.192 26.015 43.197 26.285 ;
     RECT  10.296 26.249 24.822 26.393 ;
     RECT  26.676 25.619 26.997 26.393 ;
     RECT  25.668 26.015 25.686 26.429 ;
     RECT  10.296 26.393 22.986 26.519 ;
     RECT  23.76 26.393 24.822 26.519 ;
     RECT  33.192 26.285 36.486 26.519 ;
     RECT  37.515 26.285 43.197 26.519 ;
     RECT  10.332 26.519 22.914 26.555 ;
     RECT  10.332 26.555 22.446 26.591 ;
     RECT  34.164 26.519 36.486 26.627 ;
     RECT  37.515 26.519 39.006 26.627 ;
     RECT  33.192 26.519 33.21 26.663 ;
     RECT  34.2 26.627 36.486 26.663 ;
     RECT  37.515 26.627 38.178 26.663 ;
     RECT  38.988 26.627 39.006 26.663 ;
     RECT  42.264 26.519 43.197 26.663 ;
     RECT  40.104 26.519 41.526 26.669 ;
     RECT  40.104 26.669 41.058 26.672 ;
     RECT  2.415 15.755 2.697 26.747 ;
     RECT  5.115 20.345 5.397 26.747 ;
     RECT  7.815 25.205 8.097 26.747 ;
     RECT  24.015 26.519 24.297 26.747 ;
     RECT  26.715 26.393 26.997 26.747 ;
     RECT  29.415 26.015 29.697 26.747 ;
     RECT  32.115 25.979 32.397 26.747 ;
     RECT  37.515 26.663 37.797 26.747 ;
     RECT  40.215 26.672 41.058 26.747 ;
     RECT  42.372 26.663 43.197 26.747 ;
     RECT  45.615 25.583 45.897 26.747 ;
     RECT  48.315 24.701 48.597 26.747 ;
     RECT  51.015 18.023 51.297 26.747 ;
     RECT  53.715 18.221 53.997 26.747 ;
     RECT  56.415 18.149 56.697 26.747 ;
     RECT  59.115 19.229 59.397 26.747 ;
     RECT  61.815 19.265 62.097 26.747 ;
     RECT  10.332 26.591 22.41 26.789 ;
     RECT  34.815 26.663 36.486 26.789 ;
     RECT  41.04 26.747 41.058 26.789 ;
     RECT  42.372 26.747 43.005 26.789 ;
     RECT  35.892 26.789 36.054 26.825 ;
     RECT  10.476 26.789 22.41 26.861 ;
     RECT  36.036 26.825 36.054 26.861 ;
     RECT  10.476 26.861 21.942 26.969 ;
     RECT  2.415 26.747 2.505 27.017 ;
     RECT  5.115 26.747 5.205 27.017 ;
     RECT  7.815 26.747 7.905 27.017 ;
     RECT  24.015 26.747 24.105 27.017 ;
     RECT  26.715 26.747 26.805 27.017 ;
     RECT  29.415 26.747 29.505 27.017 ;
     RECT  32.115 26.747 32.205 27.017 ;
     RECT  34.815 26.789 34.905 27.017 ;
     RECT  37.515 26.747 37.605 27.017 ;
     RECT  40.215 26.747 40.305 27.017 ;
     RECT  42.915 26.789 43.005 27.017 ;
     RECT  45.615 26.747 45.705 27.017 ;
     RECT  48.315 26.747 48.405 27.017 ;
     RECT  51.015 26.747 51.105 27.017 ;
     RECT  53.715 26.747 53.805 27.017 ;
     RECT  56.415 26.747 56.505 27.017 ;
     RECT  59.115 26.747 59.205 27.017 ;
     RECT  61.815 26.747 61.905 27.017 ;
     RECT  10.476 26.969 19.602 27.293 ;
     RECT  20.376 26.969 21.942 27.293 ;
     RECT  10.476 27.293 19.386 27.341 ;
     RECT  20.484 27.293 21.942 27.341 ;
     RECT  10.476 27.341 12.51 27.389 ;
     RECT  17.568 27.341 18.234 27.389 ;
     RECT  11.124 27.389 12.51 27.917 ;
     RECT  14.22 27.341 16.326 27.965 ;
     RECT  17.568 27.389 17.586 27.965 ;
     RECT  19.116 27.341 19.134 28.493 ;
     RECT  11.232 27.917 12.51 28.541 ;
     RECT  11.556 28.541 11.97 29.021 ;
     RECT  11.556 29.021 11.79 29.069 ;
     RECT  14.904 27.965 15.39 29.069 ;
     RECT  16.308 27.965 16.326 29.069 ;
     RECT  21.924 27.341 21.942 29.069 ;
    LAYER M4 ;
     RECT  0.06 0.864 0.137 9.96 ;
     RECT  0.06 10.944 2.293 14.568 ;
     RECT  0.137 1.008 2.408 9.96 ;
     RECT  2.293 10.944 2.408 14.856 ;
     RECT  2.408 1.008 2.512 27.012 ;
     RECT  2.512 1.008 2.704 26.742 ;
     RECT  2.704 1.008 2.819 15.48 ;
     RECT  2.819 1.008 2.873 12.84 ;
     RECT  2.819 13.824 2.873 14.952 ;
     RECT  2.873 13.824 2.981 13.848 ;
     RECT  2.873 1.008 3.161 11.256 ;
     RECT  2.873 12.24 3.485 12.84 ;
     RECT  3.161 1.008 3.917 7.176 ;
     RECT  3.485 12.48 4.061 12.84 ;
     RECT  4.061 12.528 4.129 12.84 ;
     RECT  4.129 12.528 4.489 13.608 ;
     RECT  4.489 12.528 4.549 13.656 ;
     RECT  2.873 14.928 4.549 14.952 ;
     RECT  3.917 1.152 4.561 7.176 ;
     RECT  3.161 8.16 4.561 11.256 ;
     RECT  4.561 1.152 4.789 11.256 ;
     RECT  4.789 1.152 5.108 11.448 ;
     RECT  4.549 12.528 5.108 14.952 ;
     RECT  5.108 1.152 5.212 27.012 ;
     RECT  5.212 1.152 5.404 26.742 ;
     RECT  5.404 1.152 5.897 14.952 ;
     RECT  6.469 18.624 6.853 18.648 ;
     RECT  6.577 21.84 6.853 21.864 ;
     RECT  5.404 23.376 6.853 23.4 ;
     RECT  6.853 21.84 6.901 23.4 ;
     RECT  5.897 1.152 7.045 7.656 ;
     RECT  5.897 8.832 7.045 14.952 ;
     RECT  6.901 21.744 7.477 23.4 ;
     RECT  7.045 25.008 7.477 25.032 ;
     RECT  7.045 1.152 7.808 14.952 ;
     RECT  7.225 15.984 7.808 16.008 ;
     RECT  6.853 18.144 7.808 18.648 ;
     RECT  5.404 19.776 7.808 19.8 ;
     RECT  7.477 21.744 7.808 25.032 ;
     RECT  7.808 1.152 7.912 27.012 ;
     RECT  7.912 1.152 8.104 26.742 ;
     RECT  8.104 1.152 8.561 16.824 ;
     RECT  8.104 21.552 8.569 23.304 ;
     RECT  8.104 18.144 8.705 19.032 ;
     RECT  8.569 21.552 8.813 21.576 ;
     RECT  8.561 1.152 8.885 14.856 ;
     RECT  8.885 1.92 9.109 14.856 ;
     RECT  8.561 15.984 9.148 16.824 ;
     RECT  9.109 1.92 9.173 14.76 ;
     RECT  8.569 22.752 9.301 23.304 ;
     RECT  9.148 15.984 9.353 16.536 ;
     RECT  8.104 25.008 9.709 25.032 ;
     RECT  9.673 21.072 9.973 21.096 ;
     RECT  9.301 22.752 10.033 23.544 ;
     RECT  9.709 24.96 10.033 25.032 ;
     RECT  9.353 16.512 10.321 16.536 ;
     RECT  9.173 1.92 10.508 2.616 ;
     RECT  9.173 3.6 10.508 14.76 ;
     RECT  10.321 16.512 10.508 17.16 ;
     RECT  8.705 18.144 10.508 18.84 ;
     RECT  9.973 21.072 10.508 21.528 ;
     RECT  10.033 22.752 10.508 25.032 ;
     RECT  10.357 26.208 10.508 26.232 ;
     RECT  10.465 27.36 10.508 27.384 ;
     RECT  10.508 1.92 10.691 27.384 ;
     RECT  10.691 1.92 10.804 26.76 ;
     RECT  10.804 26.736 11.009 26.76 ;
     RECT  11.069 27.888 11.153 27.912 ;
     RECT  10.357 29.04 11.18 29.064 ;
     RECT  10.804 17.136 11.441 18.168 ;
     RECT  10.804 19.344 11.459 20.088 ;
     RECT  11.441 18.144 11.585 18.168 ;
     RECT  11.459 19.344 11.585 19.368 ;
     RECT  11.18 28.464 11.801 29.064 ;
     RECT  10.804 22.944 11.945 24.984 ;
     RECT  11.801 28.464 11.981 29.016 ;
     RECT  11.981 28.464 11.987 28.536 ;
     RECT  10.804 21.12 12.037 21.528 ;
     RECT  11.945 22.944 12.037 23.4 ;
     RECT  10.804 1.92 12.157 14.712 ;
     RECT  12.445 26.256 12.553 26.28 ;
     RECT  12.077 27.312 12.553 27.336 ;
     RECT  11.987 28.512 12.563 28.536 ;
     RECT  12.805 20.112 12.841 20.136 ;
     RECT  12.037 21.12 12.913 23.4 ;
     RECT  11.441 17.136 12.949 17.16 ;
     RECT  12.841 19.872 12.949 20.136 ;
     RECT  12.949 19.536 12.985 20.136 ;
     RECT  12.949 16.512 13.045 17.64 ;
     RECT  12.985 18.816 13.045 20.136 ;
     RECT  12.157 1.92 13.093 15.528 ;
     RECT  13.045 16.512 13.093 20.136 ;
     RECT  13.093 1.92 13.208 20.136 ;
     RECT  12.913 21.12 13.208 23.688 ;
     RECT  11.945 24.96 13.208 24.984 ;
     RECT  12.553 26.256 13.208 27.336 ;
     RECT  13.208 1.92 13.504 27.336 ;
     RECT  13.504 18.528 13.565 18.552 ;
     RECT  13.504 19.536 13.565 19.896 ;
     RECT  13.565 19.632 13.601 19.896 ;
     RECT  13.504 1.92 13.66 16.632 ;
     RECT  13.601 19.632 13.709 19.848 ;
     RECT  13.709 19.632 13.817 19.8 ;
     RECT  13.504 20.88 13.961 25.08 ;
     RECT  13.961 22.56 14.033 25.08 ;
     RECT  13.817 19.632 14.105 19.656 ;
     RECT  13.66 1.92 14.14 14.808 ;
     RECT  13.504 26.784 14.204 27.336 ;
     RECT  14.033 24.528 14.285 25.08 ;
     RECT  14.204 26.784 14.291 27.96 ;
     RECT  14.14 1.92 14.605 12.888 ;
     RECT  14.533 0.576 14.617 0.6 ;
     RECT  14.605 1.728 14.821 12.888 ;
     RECT  13.66 16.08 14.821 16.632 ;
     RECT  14.569 17.616 14.821 17.64 ;
     RECT  14.285 25.056 14.821 25.08 ;
     RECT  14.033 22.56 14.861 23.4 ;
     RECT  14.821 25.056 14.861 25.176 ;
     RECT  14.14 14.112 14.893 14.808 ;
     RECT  14.821 15.984 14.893 17.64 ;
     RECT  14.821 1.152 14.905 12.888 ;
     RECT  14.893 19.056 15.037 19.08 ;
     RECT  15.037 18.816 15.181 19.08 ;
     RECT  14.893 14.112 15.217 17.64 ;
     RECT  15.181 18.816 15.217 19.368 ;
     RECT  14.905 1.728 15.433 12.888 ;
     RECT  15.217 14.112 15.433 19.368 ;
     RECT  14.291 26.784 15.721 27.336 ;
     RECT  15.733 0.144 15.757 0.168 ;
     RECT  15.433 1.728 15.908 19.368 ;
     RECT  13.961 20.88 15.908 21.528 ;
     RECT  14.861 22.56 15.908 22.824 ;
     RECT  14.861 25.152 15.908 25.176 ;
     RECT  15.721 26.784 15.908 27.96 ;
     RECT  15.908 1.728 16.019 27.96 ;
     RECT  15.757 0.144 16.117 0.552 ;
     RECT  16.019 1.728 16.204 27.336 ;
     RECT  16.117 0.096 16.225 0.552 ;
     RECT  16.204 1.728 16.225 17.64 ;
     RECT  16.225 0.096 16.307 17.64 ;
     RECT  14.389 29.04 16.337 29.064 ;
     RECT  16.204 18.768 16.355 19.944 ;
     RECT  16.204 21.12 16.355 24.552 ;
     RECT  16.355 22.56 16.553 24.552 ;
     RECT  16.553 22.56 16.669 24.504 ;
     RECT  16.597 28.992 16.739 29.016 ;
     RECT  16.355 18.768 16.913 19.08 ;
     RECT  16.204 26.832 16.913 27.336 ;
     RECT  16.913 18.768 17.021 19.032 ;
     RECT  17.021 18.768 17.165 18.792 ;
     RECT  16.307 0.096 17.305 0.12 ;
     RECT  16.355 21.168 17.413 21.528 ;
     RECT  16.669 22.56 17.413 24.408 ;
     RECT  16.307 1.152 17.561 17.64 ;
     RECT  17.585 26.208 17.605 26.808 ;
     RECT  17.561 1.152 17.669 8.424 ;
     RECT  17.305 0.096 17.701 0.168 ;
     RECT  17.413 21.168 17.737 24.408 ;
     RECT  17.557 27.936 17.747 27.96 ;
     RECT  17.701 0.096 17.785 0.6 ;
     RECT  17.785 0.096 17.849 0.12 ;
     RECT  17.737 21.168 17.917 24.504 ;
     RECT  17.605 25.536 17.989 26.808 ;
     RECT  17.917 20.688 18.385 24.504 ;
     RECT  17.989 25.536 18.385 27.384 ;
     RECT  17.561 9.696 18.457 17.64 ;
     RECT  18.385 20.688 18.467 27.384 ;
     RECT  18.467 20.688 18.565 27.336 ;
     RECT  17.669 1.728 18.608 8.424 ;
     RECT  18.457 9.696 18.608 18.264 ;
     RECT  18.565 20.16 18.608 27.336 ;
     RECT  18.608 1.728 18.904 27.336 ;
     RECT  18.853 28.464 19.145 28.488 ;
     RECT  18.904 21.168 19.181 25.704 ;
     RECT  19.181 23.904 19.217 25.704 ;
     RECT  18.904 9.216 19.289 17.112 ;
     RECT  19.181 21.168 19.379 22.872 ;
     RECT  19.217 24.624 19.469 25.704 ;
     RECT  19.379 21.36 19.505 22.872 ;
     RECT  19.505 21.36 19.721 22.824 ;
     RECT  18.904 20.16 19.909 20.184 ;
     RECT  18.904 18.24 19.955 18.792 ;
     RECT  19.289 9.216 19.973 16.968 ;
     RECT  19.973 9.216 20.005 12.888 ;
     RECT  19.721 21.36 20.14 22.728 ;
     RECT  20.005 28.992 20.147 29.016 ;
     RECT  18.904 1.728 20.257 7.656 ;
     RECT  20.005 8.976 20.257 12.888 ;
     RECT  19.973 13.872 20.257 16.968 ;
     RECT  19.469 25.104 20.437 25.704 ;
     RECT  18.904 26.784 20.437 27.336 ;
     RECT  20.437 25.104 20.485 27.336 ;
     RECT  20.257 1.728 20.521 12.888 ;
     RECT  20.257 13.872 20.617 17.208 ;
     RECT  20.521 1.92 21.049 12.888 ;
     RECT  20.617 13.872 21.049 18.024 ;
     RECT  20.14 21.696 21.061 22.728 ;
     RECT  20.485 24.432 21.061 27.336 ;
     RECT  19.909 19.776 21.157 20.184 ;
     RECT  21.061 21.696 21.269 27.336 ;
     RECT  21.049 1.92 21.308 18.024 ;
     RECT  21.157 19.344 21.308 20.184 ;
     RECT  21.269 21.696 21.308 27.012 ;
     RECT  21.308 1.92 21.412 27.012 ;
     RECT  21.412 1.92 21.604 26.742 ;
     RECT  21.604 19.776 21.665 26.28 ;
     RECT  21.301 29.04 21.953 29.064 ;
     RECT  21.665 21.12 21.989 26.28 ;
     RECT  20.293 0.096 22.313 0.12 ;
     RECT  21.989 21.12 22.313 24.648 ;
     RECT  21.604 1.92 22.349 8.52 ;
     RECT  21.604 9.6 22.565 13.128 ;
     RECT  22.565 9.792 22.633 13.128 ;
     RECT  21.604 14.112 22.633 18.024 ;
     RECT  22.313 21.12 22.709 24.504 ;
     RECT  22.709 21.408 22.781 24.504 ;
     RECT  21.989 26.208 22.789 26.28 ;
     RECT  22.789 26.208 22.997 26.376 ;
     RECT  22.633 9.792 23.033 18.024 ;
     RECT  21.665 19.776 23.497 19.944 ;
     RECT  22.781 21.408 23.785 22.776 ;
     RECT  22.781 23.904 23.857 24.504 ;
     RECT  22.349 1.92 23.893 8.28 ;
     RECT  23.497 19.392 23.893 19.944 ;
     RECT  23.785 21.12 23.893 22.776 ;
     RECT  23.857 23.904 24.001 24.744 ;
     RECT  23.893 1.92 24.008 8.52 ;
     RECT  23.033 9.792 24.008 12.84 ;
     RECT  23.033 14.112 24.008 18.024 ;
     RECT  23.893 19.392 24.008 22.824 ;
     RECT  24.001 23.904 24.008 25.224 ;
     RECT  22.997 26.208 24.008 26.28 ;
     RECT  24.008 1.92 24.112 27.012 ;
     RECT  24.112 1.92 24.304 26.742 ;
     RECT  24.304 1.92 24.419 18.216 ;
     RECT  24.304 19.536 24.419 25.224 ;
     RECT  24.419 19.728 24.617 25.224 ;
     RECT  24.617 21.6 24.659 25.224 ;
     RECT  24.419 8.496 24.797 18.216 ;
     RECT  24.659 21.6 24.797 24.744 ;
     RECT  24.304 26.208 24.866 26.28 ;
     RECT  24.797 9.024 25.085 18.216 ;
     RECT  24.797 21.6 25.187 23.88 ;
     RECT  25.187 22.176 25.571 23.88 ;
     RECT  24.866 26.208 25.571 26.232 ;
     RECT  24.617 19.728 25.661 20.616 ;
     RECT  24.419 1.92 26.117 7.512 ;
     RECT  25.661 19.776 26.233 20.616 ;
     RECT  25.085 9.264 26.557 18.216 ;
     RECT  26.117 1.92 26.708 7.56 ;
     RECT  26.557 9.072 26.708 18.216 ;
     RECT  26.233 19.776 26.708 20.904 ;
     RECT  25.571 22.464 26.708 23.88 ;
     RECT  26.557 25.296 26.708 25.32 ;
     RECT  26.708 1.92 26.812 27.012 ;
     RECT  26.812 1.92 27.004 26.742 ;
     RECT  27.004 20.832 27.065 25.32 ;
     RECT  27.065 20.832 27.155 25.224 ;
     RECT  27.004 1.92 27.245 8.472 ;
     RECT  27.245 1.92 27.317 6.312 ;
     RECT  27.004 9.792 27.389 19.8 ;
     RECT  27.389 19.296 27.461 19.8 ;
     RECT  27.155 22.128 27.677 25.224 ;
     RECT  27.389 9.792 27.965 18.168 ;
     RECT  27.677 22.128 28.037 24.552 ;
     RECT  27.965 9.792 28.217 17.496 ;
     RECT  27.461 19.776 28.249 19.8 ;
     RECT  27.155 20.832 28.249 20.856 ;
     RECT  27.245 7.392 28.289 8.472 ;
     RECT  28.289 7.392 28.501 7.992 ;
     RECT  28.501 7.296 28.681 7.992 ;
     RECT  27.317 1.92 28.753 6.12 ;
     RECT  28.681 7.104 28.753 7.992 ;
     RECT  28.217 9.888 29.005 17.496 ;
     RECT  28.825 18.624 29.005 18.648 ;
     RECT  28.249 19.776 29.329 20.856 ;
     RECT  29.329 19.776 29.365 20.904 ;
     RECT  28.753 1.92 29.408 7.992 ;
     RECT  29.005 9.888 29.408 18.648 ;
     RECT  29.365 19.776 29.408 21 ;
     RECT  28.037 22.32 29.408 24.552 ;
     RECT  28.105 25.776 29.408 25.8 ;
     RECT  29.408 1.92 29.512 27.012 ;
     RECT  29.512 1.92 29.704 26.742 ;
     RECT  29.704 1.92 30.349 7.992 ;
     RECT  29.704 22.608 30.485 23.832 ;
     RECT  29.704 25.68 30.521 25.8 ;
     RECT  30.349 1.92 30.737 7.8 ;
     RECT  30.485 22.608 30.769 23.592 ;
     RECT  29.704 20.016 30.881 21.144 ;
     RECT  29.704 9.36 30.949 17.496 ;
     RECT  30.949 9.312 30.953 17.496 ;
     RECT  30.881 20.016 31.309 20.04 ;
     RECT  30.953 9.312 31.561 9.336 ;
     RECT  30.737 1.92 32.108 7.704 ;
     RECT  31.561 8.928 32.108 9.336 ;
     RECT  30.953 10.368 32.108 17.496 ;
     RECT  31.309 19.584 32.108 20.04 ;
     RECT  30.881 21.12 32.108 21.144 ;
     RECT  30.769 22.512 32.108 23.592 ;
     RECT  32.101 24.624 32.108 24.648 ;
     RECT  30.521 25.68 32.108 25.704 ;
     RECT  32.108 1.92 32.212 27.012 ;
     RECT  32.212 1.92 32.404 26.742 ;
     RECT  32.404 9.312 32.609 9.336 ;
     RECT  32.404 21.216 32.825 25.704 ;
     RECT  32.825 22.368 33.244 25.704 ;
     RECT  32.404 7.344 33.401 7.896 ;
     RECT  32.404 10.368 33.685 18.744 ;
     RECT  32.404 19.776 33.685 19.896 ;
     RECT  32.825 21.216 33.685 21.384 ;
     RECT  33.685 10.368 33.829 19.896 ;
     RECT  33.685 20.976 33.829 21.384 ;
     RECT  32.404 1.92 34.161 6.264 ;
     RECT  33.401 7.344 34.161 7.752 ;
     RECT  33.829 10.368 34.333 21.384 ;
     RECT  33.244 22.368 34.333 25.08 ;
     RECT  34.069 9.072 34.369 9.096 ;
     RECT  34.045 26.256 34.441 26.28 ;
     RECT  34.161 1.92 34.477 7.752 ;
     RECT  34.369 8.736 34.477 9.096 ;
     RECT  34.477 1.92 34.808 9.096 ;
     RECT  34.333 10.368 34.808 25.08 ;
     RECT  34.441 26.064 34.808 26.28 ;
     RECT  34.808 1.92 34.912 27.012 ;
     RECT  34.912 1.92 35.104 26.742 ;
     RECT  35.104 19.248 35.237 23.064 ;
     RECT  35.237 19.248 35.363 22.536 ;
     RECT  35.104 1.92 36.253 8.232 ;
     RECT  36.253 3.6 36.38 8.232 ;
     RECT  36.38 3.6 36.467 8.472 ;
     RECT  36.467 3.6 36.497 8.232 ;
     RECT  35.104 24.24 36.524 26.28 ;
     RECT  35.104 9.792 36.745 18.264 ;
     RECT  35.363 19.776 36.745 22.536 ;
     RECT  36.524 23.664 37.213 26.28 ;
     RECT  36.253 1.92 37.393 2.616 ;
     RECT  36.497 3.6 37.393 7.704 ;
     RECT  36.745 9.792 37.429 22.536 ;
     RECT  37.393 1.92 37.508 7.704 ;
     RECT  37.429 9.504 37.508 22.536 ;
     RECT  37.213 23.568 37.508 26.28 ;
     RECT  37.508 1.92 37.612 27.012 ;
     RECT  37.612 1.92 37.804 26.742 ;
     RECT  37.804 1.92 38.009 18.792 ;
     RECT  37.804 24.48 38.189 26.28 ;
     RECT  38.401 0.192 38.437 0.216 ;
     RECT  38.009 9.504 38.819 18.792 ;
     RECT  37.804 22.32 38.861 23.16 ;
     RECT  38.189 24.48 38.861 25.608 ;
     RECT  38.437 0.096 38.869 0.216 ;
     RECT  38.861 22.32 38.945 25.608 ;
     RECT  38.009 1.92 39.013 8.52 ;
     RECT  38.945 22.32 39.017 22.92 ;
     RECT  39.017 22.512 39.053 22.92 ;
     RECT  37.804 19.776 39.121 21.096 ;
     RECT  39.013 1.92 39.197 8.712 ;
     RECT  38.869 0.096 39.337 0.6 ;
     RECT  39.197 1.92 39.337 7.992 ;
     RECT  38.945 24.48 39.373 25.608 ;
     RECT  39.373 24.48 39.404 26.04 ;
     RECT  39.337 0.096 39.529 7.992 ;
     RECT  39.404 24.48 40.021 26.088 ;
     RECT  39.121 19.776 40.057 21.432 ;
     RECT  39.053 22.512 40.057 22.776 ;
     RECT  40.021 24.48 40.093 26.376 ;
     RECT  39.529 1.104 40.208 7.992 ;
     RECT  38.819 9.792 40.208 18.792 ;
     RECT  40.057 19.776 40.208 22.776 ;
     RECT  40.093 24.48 40.208 26.664 ;
     RECT  40.208 1.104 40.312 27.012 ;
     RECT  40.312 1.104 40.504 26.742 ;
     RECT  40.504 1.104 40.565 8.184 ;
     RECT  40.504 10.08 40.997 19.08 ;
     RECT  39.529 0.096 41.069 0.12 ;
     RECT  40.504 21.936 41.285 22.056 ;
     RECT  40.997 18.768 41.315 19.08 ;
     RECT  40.997 10.08 41.321 17.688 ;
     RECT  40.565 1.152 41.501 6.408 ;
     RECT  41.501 1.248 41.509 6.408 ;
     RECT  40.504 23.664 41.537 26.664 ;
     RECT  41.509 1.632 41.653 6.408 ;
     RECT  40.565 7.392 41.653 8.184 ;
     RECT  41.321 10.08 41.713 17.496 ;
     RECT  41.537 23.664 41.713 26.232 ;
     RECT  41.315 18.96 42.001 19.08 ;
     RECT  40.504 20.16 42.001 20.904 ;
     RECT  41.653 1.632 42.113 8.184 ;
     RECT  42.001 18.96 42.217 20.904 ;
     RECT  41.285 21.936 42.217 21.96 ;
     RECT  42.217 18.96 42.325 21.96 ;
     RECT  41.713 9.888 42.685 17.496 ;
     RECT  42.325 18.528 42.685 21.96 ;
     RECT  42.685 9.888 42.709 21.96 ;
     RECT  42.709 9.264 42.793 21.96 ;
     RECT  42.113 1.728 42.908 8.184 ;
     RECT  42.793 9.264 42.908 22.056 ;
     RECT  41.713 23.328 42.908 26.232 ;
     RECT  42.757 0.096 42.947 0.312 ;
     RECT  42.908 1.728 43.012 27.012 ;
     RECT  43.012 1.728 43.204 26.742 ;
     RECT  43.204 24.48 43.301 25.512 ;
     RECT  42.947 0.096 43.337 0.168 ;
     RECT  43.204 20.592 43.337 22.344 ;
     RECT  43.337 20.592 43.373 21 ;
     RECT  43.301 24.48 43.373 25.32 ;
     RECT  43.204 1.728 43.811 19.416 ;
     RECT  43.337 22.32 43.955 22.344 ;
     RECT  43.373 20.688 44.021 21 ;
     RECT  43.204 23.328 44.057 23.352 ;
     RECT  43.337 0.144 44.093 0.168 ;
     RECT  43.811 19.392 44.129 19.416 ;
     RECT  43.811 1.728 44.381 17.928 ;
     RECT  44.381 1.728 44.633 17.736 ;
     RECT  43.373 24.48 44.917 24.936 ;
     RECT  44.021 20.688 44.989 20.712 ;
     RECT  44.633 1.728 45.608 9.288 ;
     RECT  44.633 10.32 45.608 17.736 ;
     RECT  44.989 20.352 45.608 20.712 ;
     RECT  44.665 21.696 45.608 21.768 ;
     RECT  44.917 24.48 45.608 25.032 ;
     RECT  45.608 1.728 45.712 27.012 ;
     RECT  45.712 1.728 45.904 26.742 ;
     RECT  45.637 0.144 45.925 0.168 ;
     RECT  45.925 0.144 46.021 0.264 ;
     RECT  45.904 10.656 46.037 19.272 ;
     RECT  46.021 0.144 46.069 0.552 ;
     RECT  45.904 20.64 46.109 20.712 ;
     RECT  45.904 24.48 46.325 24.504 ;
     RECT  46.069 0.096 46.403 0.552 ;
     RECT  45.904 23.328 46.547 23.352 ;
     RECT  46.037 10.656 46.739 19.08 ;
     RECT  45.904 22.224 46.829 22.248 ;
     RECT  46.403 0.096 46.901 0.12 ;
     RECT  45.904 1.728 46.933 9.528 ;
     RECT  46.739 10.656 46.933 18.888 ;
     RECT  46.109 20.64 47.261 20.664 ;
     RECT  48.181 0.192 48.229 0.216 ;
     RECT  46.933 1.728 48.308 18.888 ;
     RECT  48.308 1.728 48.412 27.012 ;
     RECT  48.412 1.728 48.445 26.742 ;
     RECT  48.445 1.68 48.563 26.742 ;
     RECT  48.563 1.728 48.604 26.742 ;
     RECT  48.229 0.096 48.805 0.216 ;
     RECT  48.604 1.728 48.917 18.024 ;
     RECT  48.805 0.096 49.741 0.264 ;
     RECT  49.741 0.096 50.029 0.504 ;
     RECT  50.029 0.096 50.147 0.552 ;
     RECT  48.917 1.728 50.245 17.496 ;
     RECT  50.245 1.68 50.389 17.496 ;
     RECT  50.389 1.632 50.579 17.496 ;
     RECT  50.579 1.728 50.741 17.496 ;
     RECT  50.741 1.728 51.008 17.688 ;
     RECT  50.147 0.096 51.011 0.504 ;
     RECT  51.008 1.728 51.112 27.012 ;
     RECT  51.112 1.728 51.304 26.742 ;
     RECT  51.304 1.728 51.877 1.752 ;
     RECT  51.011 0.096 52.265 0.168 ;
     RECT  51.304 2.88 52.364 17.496 ;
     RECT  52.693 0.288 53.269 0.6 ;
     RECT  53.269 0.288 53.365 1.176 ;
     RECT  52.364 2.256 53.365 17.496 ;
     RECT  53.365 0.288 53.413 17.496 ;
     RECT  53.413 0.192 53.557 17.496 ;
     RECT  53.557 0.144 53.708 17.496 ;
     RECT  53.708 0.144 53.812 27.012 ;
     RECT  53.812 0.144 54.004 26.742 ;
     RECT  54.004 0.144 54.029 17.832 ;
     RECT  54.029 0.144 54.101 0.552 ;
     RECT  54.101 0.144 54.133 0.312 ;
     RECT  54.029 1.728 54.785 17.832 ;
     RECT  54.133 0.096 55.249 0.312 ;
     RECT  55.249 0.096 55.763 0.552 ;
     RECT  54.785 1.728 55.813 17.784 ;
     RECT  55.813 1.728 56.408 17.976 ;
     RECT  56.408 1.728 56.512 27.012 ;
     RECT  56.512 1.728 56.704 26.742 ;
     RECT  55.763 0.096 56.773 0.216 ;
     RECT  56.704 1.728 56.773 18.216 ;
     RECT  56.773 0.096 56.873 18.216 ;
     RECT  56.873 0.144 56.915 18.216 ;
     RECT  56.915 0.144 56.945 0.504 ;
     RECT  56.915 1.728 57.949 18.216 ;
     RECT  56.945 0.192 58.268 0.504 ;
     RECT  58.268 0.192 58.355 0.552 ;
     RECT  58.355 0.192 59.075 0.504 ;
     RECT  57.949 1.728 59.108 18.264 ;
     RECT  59.108 1.728 59.212 27.012 ;
     RECT  59.212 1.728 59.404 26.742 ;
     RECT  59.404 1.728 59.509 15.48 ;
     RECT  59.173 0.096 59.555 0.168 ;
     RECT  59.509 1.152 59.573 15.48 ;
     RECT  59.573 1.152 59.645 15.432 ;
     RECT  59.645 1.152 59.651 9.72 ;
     RECT  59.555 0.096 59.717 0.12 ;
     RECT  59.645 10.992 59.761 15.432 ;
     RECT  59.404 18.24 59.789 18.264 ;
     RECT  59.761 10.992 59.933 14.52 ;
     RECT  59.933 10.992 60.041 14.28 ;
     RECT  59.651 1.152 60.077 9.288 ;
     RECT  60.041 10.992 60.077 13.848 ;
     RECT  60.077 13.2 60.473 13.848 ;
     RECT  60.077 10.992 60.901 12.216 ;
     RECT  60.077 1.152 60.947 8.952 ;
     RECT  60.901 10.368 61.405 12.216 ;
     RECT  60.473 13.2 61.405 13.8 ;
     RECT  61.333 0.096 61.669 0.12 ;
     RECT  60.947 1.728 61.808 8.952 ;
     RECT  61.405 10.368 61.808 13.8 ;
     RECT  60.721 16.8 61.808 16.824 ;
     RECT  61.808 1.728 61.912 27.012 ;
     RECT  61.669 0.096 62.053 0.168 ;
     RECT  61.912 1.728 62.104 26.742 ;
     RECT  62.053 0.096 62.201 0.216 ;
     RECT  62.104 1.728 62.273 4.008 ;
     RECT  62.273 1.824 62.309 4.008 ;
     RECT  62.104 5.04 62.345 8.808 ;
     RECT  62.201 0.096 62.525 0.12 ;
     RECT  62.309 2.256 62.531 4.008 ;
     RECT  62.531 2.88 62.675 4.008 ;
     RECT  62.675 2.88 62.723 3.048 ;
     RECT  62.723 2.88 62.819 2.904 ;
     RECT  62.345 5.328 63.133 8.808 ;
     RECT  63.133 5.328 63.169 9.384 ;
     RECT  62.104 10.368 63.169 13.848 ;
     RECT  62.104 14.832 63.169 15.144 ;
     RECT  62.104 16.416 63.169 16.728 ;
     RECT  63.169 5.328 63.205 13.848 ;
     RECT  63.169 14.832 63.205 16.728 ;
     RECT  63.205 5.328 63.241 16.728 ;
     RECT  62.104 18 63.241 18.024 ;
     RECT  63.241 5.328 64.573 18.024 ;
     RECT  64.573 5.328 64.764 18.168 ;
    LAYER M5 ;
     RECT  38.736 0.016 57.048 0.131 ;
     RECT  58.32 0.016 62.808 0.563 ;
     RECT  14.544 0.016 20.472 0.611 ;
     RECT  38.88 0.131 57.048 0.611 ;
     RECT  14.688 0.611 20.472 1.763 ;
     RECT  39.312 0.611 57.048 1.763 ;
     RECT  15.12 1.763 16.584 1.811 ;
     RECT  18.144 1.763 19.896 1.811 ;
     RECT  15.264 1.811 16.584 1.859 ;
     RECT  18.144 1.811 19.752 1.859 ;
     RECT  39.312 1.763 40.92 1.909 ;
     RECT  23.904 2.053 23.928 2.137 ;
     RECT  58.464 0.563 62.808 2.149 ;
     RECT  2.4 2.137 2.52 2.151 ;
     RECT  5.1 2.137 5.22 2.151 ;
     RECT  7.8 2.137 7.92 2.151 ;
     RECT  10.5 2.137 10.62 2.151 ;
     RECT  13.2 2.137 13.32 2.151 ;
     RECT  21.3 2.137 21.42 2.151 ;
     RECT  23.904 2.137 24.12 2.151 ;
     RECT  26.7 2.137 26.82 2.151 ;
     RECT  29.4 2.137 29.52 2.151 ;
     RECT  32.1 2.137 32.22 2.151 ;
     RECT  34.8 2.137 34.92 2.151 ;
     RECT  37.5 2.137 37.62 2.151 ;
     RECT  41.904 1.763 57.048 2.197 ;
     RECT  58.416 2.149 62.808 2.197 ;
     RECT  23.904 2.151 24.312 2.243 ;
     RECT  18.6 1.859 19.752 2.339 ;
     RECT  41.904 2.197 62.808 2.339 ;
     RECT  29.4 2.151 29.712 2.341 ;
     RECT  18.6 2.339 19.608 2.387 ;
     RECT  26.7 2.151 27.012 2.485 ;
     RECT  26.448 2.485 27.012 2.627 ;
     RECT  29.4 2.341 30.456 2.627 ;
     RECT  21.3 2.151 21.612 2.773 ;
     RECT  5.1 2.151 5.412 2.821 ;
     RECT  33.6 2.581 33.72 2.867 ;
     RECT  15.744 1.859 16.584 2.915 ;
     RECT  53.376 2.339 62.808 2.915 ;
     RECT  41.904 2.339 52.296 2.963 ;
     RECT  53.376 2.915 62.712 3.059 ;
     RECT  41.904 2.963 44.376 3.155 ;
     RECT  45.504 2.963 52.296 3.347 ;
     RECT  45.6 3.347 52.296 3.349 ;
     RECT  53.376 3.059 62.664 3.349 ;
     RECT  36.192 2.245 36.216 3.443 ;
     RECT  15.9 2.915 16.584 3.491 ;
     RECT  29.4 2.627 30.264 3.491 ;
     RECT  45.6 3.349 62.664 3.491 ;
     RECT  39.024 1.909 40.92 4.019 ;
     RECT  53.088 3.491 62.664 4.019 ;
     RECT  37.5 2.151 37.812 4.165 ;
     RECT  21.168 2.773 21.612 4.213 ;
     RECT  41.904 3.155 44.184 4.213 ;
     RECT  22.8 4.165 22.824 4.307 ;
     RECT  41.904 4.213 44.472 4.309 ;
     RECT  34.8 2.151 35.112 4.405 ;
     RECT  20.976 4.213 21.612 4.453 ;
     RECT  22.896 4.357 22.92 4.499 ;
     RECT  37.5 4.165 37.992 4.499 ;
     RECT  18.6 2.387 18.912 4.549 ;
     RECT  20.352 4.453 21.612 4.595 ;
     RECT  33.6 2.867 33.624 4.643 ;
     RECT  25.44 4.693 25.464 4.835 ;
     RECT  24 2.243 24.312 4.885 ;
     RECT  15.9 3.491 16.212 4.933 ;
     RECT  23.904 4.885 24.312 4.981 ;
     RECT  23.904 4.981 25.416 5.027 ;
     RECT  5.1 2.821 6.168 5.077 ;
     RECT  7.8 2.151 8.112 5.077 ;
     RECT  12.048 3.397 12.072 5.171 ;
     RECT  34.656 4.405 35.112 5.171 ;
     RECT  13.2 2.151 13.512 5.221 ;
     RECT  29.4 3.491 29.712 5.221 ;
     RECT  13.104 5.221 13.512 5.363 ;
     RECT  41.664 4.309 44.472 5.509 ;
     RECT  45.6 3.491 51.312 5.509 ;
     RECT  15.12 4.933 16.212 5.605 ;
     RECT  18.48 4.549 18.912 5.605 ;
     RECT  26.7 2.627 27.012 5.749 ;
     RECT  29.4 5.221 30.312 5.749 ;
     RECT  18.336 5.605 18.912 5.893 ;
     RECT  41.664 5.509 51.312 5.989 ;
     RECT  29.4 5.749 30.504 6.083 ;
     RECT  10.5 2.151 10.812 6.085 ;
     RECT  17.712 5.893 18.912 6.133 ;
     RECT  34.8 5.171 35.112 6.229 ;
     RECT  24 5.027 25.416 6.277 ;
     RECT  26.7 5.749 27.336 6.277 ;
     RECT  10.224 6.085 10.812 6.565 ;
     RECT  24 6.277 27.336 6.851 ;
     RECT  32.1 2.151 32.412 6.901 ;
     RECT  41.664 5.989 51.624 6.995 ;
     RECT  31.968 6.901 32.412 7.091 ;
     RECT  13.2 5.363 13.512 7.141 ;
     RECT  21.3 4.595 21.612 7.189 ;
     RECT  34.224 6.229 35.112 7.235 ;
     RECT  12.768 7.141 13.512 7.331 ;
     RECT  17.376 6.133 18.912 7.331 ;
     RECT  4.8 5.077 8.112 7.381 ;
     RECT  9.36 6.565 10.812 7.381 ;
     RECT  29.4 6.083 30.312 7.381 ;
     RECT  41.664 6.995 41.688 7.381 ;
     RECT  21.3 7.189 22.008 7.427 ;
     RECT  32.1 7.091 32.412 7.429 ;
     RECT  37.5 4.499 37.812 7.429 ;
     RECT  39.024 4.019 40.512 7.429 ;
     RECT  53.088 4.019 62.112 7.429 ;
     RECT  52.944 7.429 62.112 7.475 ;
     RECT  32.1 7.429 32.856 7.477 ;
     RECT  52.944 7.475 60.216 7.523 ;
     RECT  26.16 6.851 27.336 7.571 ;
     RECT  52.944 7.523 59.832 7.619 ;
     RECT  32.1 7.477 32.952 7.715 ;
     RECT  64.608 7.813 64.632 7.955 ;
     RECT  14.976 5.605 16.212 7.957 ;
     RECT  21.3 7.427 21.612 7.957 ;
     RECT  42.9 6.995 51.624 7.957 ;
     RECT  28.752 7.381 30.312 8.003 ;
     RECT  61.2 7.475 62.112 8.003 ;
     RECT  53.472 7.619 59.832 8.051 ;
     RECT  18.336 7.331 18.912 8.195 ;
     RECT  41.52 7.381 41.688 8.195 ;
     RECT  13.2 7.331 13.512 8.485 ;
     RECT  14.688 7.957 16.212 8.485 ;
     RECT  53.7 8.051 59.832 8.771 ;
     RECT  13.2 8.485 16.212 8.867 ;
     RECT  42.72 7.957 51.624 8.963 ;
     RECT  21.024 7.957 21.612 9.011 ;
     RECT  34.8 7.235 35.112 9.061 ;
     RECT  13.2 8.867 13.512 9.109 ;
     RECT  42.72 8.963 49.656 9.203 ;
     RECT  42.72 9.203 44.184 9.299 ;
     RECT  14.688 8.867 16.212 9.349 ;
     RECT  53.7 8.771 59.784 9.397 ;
     RECT  28.752 8.003 29.712 9.541 ;
     RECT  50.64 8.963 51.624 9.779 ;
     RECT  24 6.851 24.936 9.781 ;
     RECT  37.5 7.429 40.512 9.827 ;
     RECT  45.6 9.203 49.656 9.827 ;
     RECT  36.432 8.437 36.456 10.259 ;
     RECT  12.528 9.109 13.512 10.307 ;
     RECT  23.664 9.781 24.936 10.307 ;
     RECT  34.08 9.061 35.112 10.357 ;
     RECT  41.664 8.195 41.688 10.453 ;
     RECT  37.5 9.827 38.808 10.595 ;
     RECT  34.08 10.357 35.4 10.643 ;
     RECT  32.1 7.715 32.412 10.693 ;
     RECT  14.688 9.349 16.584 10.741 ;
     RECT  50.832 9.779 51.624 10.931 ;
     RECT  42.9 9.299 44.184 10.933 ;
     RECT  41.664 10.453 41.784 10.979 ;
     RECT  31.968 10.693 32.412 10.981 ;
     RECT  34.08 10.643 35.112 11.027 ;
     RECT  36.24 10.933 36.264 11.075 ;
     RECT  53.568 9.397 59.784 11.075 ;
     RECT  42.768 10.933 44.184 11.077 ;
     RECT  45.6 9.827 48.888 11.077 ;
     RECT  42.768 11.077 48.888 11.219 ;
     RECT  31.968 10.981 32.904 11.365 ;
     RECT  26.7 7.571 27.336 11.413 ;
     RECT  37.5 10.595 38.328 11.413 ;
     RECT  4.8 7.381 10.812 11.459 ;
     RECT  53.568 11.075 54.12 11.507 ;
     RECT  14.688 10.741 17.016 11.509 ;
     RECT  21.3 9.011 21.612 11.509 ;
     RECT  31.536 11.365 32.904 11.509 ;
     RECT  26.208 11.413 27.336 11.555 ;
     RECT  36.912 11.413 38.328 11.603 ;
     RECT  53.7 11.507 54.12 11.699 ;
     RECT  13.2 10.307 13.512 11.701 ;
     RECT  14.688 11.509 17.16 11.747 ;
     RECT  37.5 11.603 38.328 11.797 ;
     RECT  15.9 11.747 17.16 11.891 ;
     RECT  18.6 8.195 18.912 11.941 ;
     RECT  41.76 10.979 41.784 11.941 ;
     RECT  42.768 11.219 44.28 11.941 ;
     RECT  45.6 11.219 48.888 11.941 ;
     RECT  51 10.931 51.624 11.989 ;
     RECT  28.752 9.541 30.12 12.035 ;
     RECT  45.6 11.941 49.272 12.085 ;
     RECT  50.496 11.989 51.624 12.131 ;
     RECT  0.144 12.229 0.168 12.371 ;
     RECT  45.6 12.085 49.416 12.467 ;
     RECT  31.536 11.509 33.048 12.515 ;
     RECT  4.944 11.459 10.812 12.611 ;
     RECT  21.168 11.509 21.612 12.611 ;
     RECT  37.5 11.797 38.952 12.611 ;
     RECT  48.3 12.467 49.416 12.755 ;
     RECT  41.76 11.941 44.28 12.757 ;
     RECT  45.6 12.467 46.968 12.757 ;
     RECT  2.4 2.151 2.712 12.949 ;
     RECT  15.9 11.891 17.016 13.045 ;
     RECT  34.8 11.027 35.112 13.045 ;
     RECT  28.752 12.035 29.712 13.139 ;
     RECT  13.2 11.701 13.608 13.141 ;
     RECT  14.688 11.747 14.808 13.141 ;
     RECT  4.944 12.611 5.544 13.283 ;
     RECT  41.76 12.757 46.968 13.619 ;
     RECT  2.304 12.949 2.712 13.621 ;
     RECT  4.944 13.283 5.412 13.621 ;
     RECT  51 12.131 51.624 13.669 ;
     RECT  6.672 12.611 10.812 13.715 ;
     RECT  55.248 11.075 59.784 13.715 ;
     RECT  41.76 13.619 46.44 13.763 ;
     RECT  15.9 13.045 17.112 13.859 ;
     RECT  41.76 13.763 44.184 13.859 ;
     RECT  45.6 13.763 46.44 13.859 ;
     RECT  55.248 13.715 59.736 13.859 ;
     RECT  51 13.669 52.104 13.907 ;
     RECT  45.6 13.859 46.152 14.003 ;
     RECT  48.3 12.755 49.272 14.197 ;
     RECT  0.144 14.101 0.168 14.243 ;
     RECT  7.8 13.715 10.812 14.291 ;
     RECT  13.2 13.141 14.808 14.291 ;
     RECT  31.536 12.515 32.412 14.291 ;
     RECT  42.384 13.859 44.184 14.291 ;
     RECT  55.536 13.859 59.736 14.291 ;
     RECT  55.776 14.291 59.736 14.339 ;
     RECT  18.6 11.941 19.56 14.341 ;
     RECT  4.56 13.621 5.412 14.435 ;
     RECT  6.672 13.715 6.696 14.435 ;
     RECT  34.8 13.045 35.352 14.485 ;
     RECT  18.6 14.341 19.656 14.821 ;
     RECT  2.304 13.621 2.808 14.867 ;
     RECT  7.8 14.291 9.096 14.867 ;
     RECT  48.192 14.197 49.272 14.917 ;
     RECT  18.6 14.821 19.752 14.963 ;
     RECT  32.1 14.291 32.412 15.397 ;
     RECT  34.8 14.485 35.928 15.443 ;
     RECT  37.5 12.611 38.328 15.443 ;
     RECT  55.824 14.339 59.736 15.443 ;
     RECT  42.432 14.291 44.184 15.445 ;
     RECT  45.6 14.003 45.912 15.445 ;
     RECT  2.4 14.867 2.808 15.491 ;
     RECT  23.664 10.307 24.84 15.493 ;
     RECT  40.2 9.827 40.512 15.829 ;
     RECT  42.432 15.445 46.296 15.829 ;
     RECT  47.328 14.917 49.272 15.925 ;
     RECT  7.8 14.867 8.52 15.973 ;
     RECT  55.824 15.443 59.412 16.019 ;
     RECT  23.568 15.493 24.84 16.021 ;
     RECT  42.432 15.829 46.344 16.067 ;
     RECT  40.2 15.829 40.632 16.069 ;
     RECT  45.6 16.067 46.344 16.069 ;
     RECT  47.328 15.925 49.56 16.069 ;
     RECT  22.8 16.021 24.84 16.211 ;
     RECT  37.5 15.443 37.812 16.213 ;
     RECT  45.6 16.069 49.56 16.403 ;
     RECT  58.128 16.019 59.412 16.595 ;
     RECT  15.9 13.859 16.212 16.597 ;
     RECT  14.784 14.291 14.808 16.643 ;
     RECT  47.328 16.403 49.56 16.643 ;
     RECT  39.024 16.597 39.048 16.739 ;
     RECT  37.392 16.213 37.812 16.789 ;
     RECT  53.7 11.699 54.012 16.789 ;
     RECT  7.8 15.973 9.096 16.835 ;
     RECT  15.9 16.597 17.112 16.835 ;
     RECT  42.432 16.067 44.328 16.835 ;
     RECT  47.328 16.643 49.272 16.835 ;
     RECT  31.872 15.397 32.412 16.931 ;
     RECT  51 13.907 51.312 16.933 ;
     RECT  40.2 16.069 41.064 17.029 ;
     RECT  53.04 16.789 54.012 17.029 ;
     RECT  55.824 16.019 56.712 17.029 ;
     RECT  42.432 16.835 43.8 17.075 ;
     RECT  26.7 11.555 27.336 17.077 ;
     RECT  37.056 16.789 37.812 17.077 ;
     RECT  33.648 15.877 33.672 17.123 ;
     RECT  53.04 17.029 56.712 17.123 ;
     RECT  58.848 16.595 59.412 17.123 ;
     RECT  34.8 15.443 35.112 17.125 ;
     RECT  22.944 16.211 24.84 17.267 ;
     RECT  42.768 17.075 43.8 17.267 ;
     RECT  23.712 17.267 24.84 17.413 ;
     RECT  13.2 14.291 13.704 17.605 ;
     RECT  15.9 16.835 16.212 17.605 ;
     RECT  29.04 13.139 29.712 17.699 ;
     RECT  50.784 16.933 51.312 17.699 ;
     RECT  53.7 17.123 56.712 17.795 ;
     RECT  55.824 17.795 56.712 17.987 ;
     RECT  45.6 16.403 46.008 17.989 ;
     RECT  47.328 16.835 48.612 17.989 ;
     RECT  45.6 17.989 48.612 18.035 ;
     RECT  7.8 16.835 8.232 18.133 ;
     RECT  40.2 17.029 41.304 18.133 ;
     RECT  6.864 18.133 8.232 18.179 ;
     RECT  26.7 17.077 27.48 18.179 ;
     RECT  15.744 17.605 16.212 18.181 ;
     RECT  26.7 18.179 27.336 18.275 ;
     RECT  29.088 17.699 29.712 18.275 ;
     RECT  37.008 17.077 37.812 18.275 ;
     RECT  18.6 14.963 19.656 18.371 ;
     RECT  13.056 17.605 13.704 18.563 ;
     RECT  10.5 14.291 10.812 18.757 ;
     RECT  42.9 17.267 43.8 18.757 ;
     RECT  26.7 18.275 27.24 18.851 ;
     RECT  15.504 18.181 16.212 19.091 ;
     RECT  45.6 18.035 46.728 19.091 ;
     RECT  9.984 18.757 10.812 19.333 ;
     RECT  21.3 12.611 21.612 19.333 ;
     RECT  15.792 19.091 16.212 19.379 ;
     RECT  23.712 17.413 25.56 19.427 ;
     RECT  42.768 18.757 43.8 19.427 ;
     RECT  6.864 18.179 8.112 19.811 ;
     RECT  39.456 18.133 41.304 19.811 ;
     RECT  42.768 19.427 43.32 19.813 ;
     RECT  15.9 19.379 16.212 19.909 ;
     RECT  34.8 17.125 35.352 20.003 ;
     RECT  9.984 19.333 11.448 20.099 ;
     RECT  19.92 18.757 19.944 20.149 ;
     RECT  21.168 19.333 21.612 20.195 ;
     RECT  24 19.427 25.56 20.389 ;
     RECT  42.288 19.813 43.32 20.723 ;
     RECT  34.8 20.003 35.112 20.725 ;
     RECT  26.7 18.851 27.012 20.869 ;
     RECT  18.6 18.371 18.912 21.157 ;
     RECT  19.92 20.149 20.088 21.157 ;
     RECT  15.9 19.909 16.344 21.299 ;
     RECT  33.84 20.725 35.112 21.395 ;
     RECT  23.904 20.389 25.56 21.493 ;
     RECT  7.8 19.811 8.112 21.541 ;
     RECT  26.7 20.869 27.144 21.683 ;
     RECT  7.8 21.541 8.52 21.733 ;
     RECT  18.6 21.157 20.088 22.069 ;
     RECT  34.704 21.395 35.112 22.115 ;
     RECT  17.904 22.069 20.088 22.117 ;
     RECT  21.3 20.195 21.612 22.117 ;
     RECT  45.6 19.091 45.912 22.213 ;
     RECT  6.912 21.733 8.52 22.259 ;
     RECT  23.712 21.493 25.56 22.307 ;
     RECT  15.9 21.299 16.212 22.309 ;
     RECT  42.768 20.723 43.32 22.309 ;
     RECT  23.904 22.307 25.56 22.355 ;
     RECT  32.1 16.931 32.412 22.549 ;
     RECT  25.536 22.355 25.56 22.693 ;
     RECT  6.912 22.259 8.112 22.741 ;
     RECT  9.984 20.099 10.812 22.741 ;
     RECT  32.1 22.549 33.336 22.741 ;
     RECT  9.312 22.741 10.812 22.835 ;
     RECT  23.904 22.355 24.552 22.835 ;
     RECT  12.048 22.357 12.072 22.979 ;
     RECT  17.904 22.117 21.612 23.075 ;
     RECT  24 22.835 24.552 23.075 ;
     RECT  15.9 22.309 16.344 23.267 ;
     RECT  42.768 22.309 43.944 23.363 ;
     RECT  45.6 22.213 46.536 23.363 ;
     RECT  10.5 22.835 10.812 23.365 ;
     RECT  6.864 22.741 8.112 23.411 ;
     RECT  9.312 22.835 9.336 23.555 ;
     RECT  25.536 22.693 25.656 23.555 ;
     RECT  31.248 22.741 33.336 23.603 ;
     RECT  37.5 18.275 37.812 23.653 ;
     RECT  42.768 23.363 43.212 23.891 ;
     RECT  10.5 23.365 11.064 23.987 ;
     RECT  32.1 23.603 33.336 23.987 ;
     RECT  40.2 19.811 41.304 24.421 ;
     RECT  15.9 23.267 16.212 24.469 ;
     RECT  24 23.075 24.312 24.469 ;
     RECT  25.536 23.555 25.56 24.469 ;
     RECT  36.576 23.653 37.812 24.563 ;
     RECT  38.88 23.893 38.904 24.613 ;
     RECT  40.2 24.421 41.784 24.613 ;
     RECT  38.88 24.613 41.784 24.659 ;
     RECT  39.456 24.659 41.784 24.947 ;
     RECT  24 24.469 25.56 25.235 ;
     RECT  18.48 23.075 21.612 25.477 ;
     RECT  18.48 25.477 21.864 25.525 ;
     RECT  17.616 25.525 21.864 25.715 ;
     RECT  32.1 23.987 33.192 25.715 ;
     RECT  41.76 24.947 41.784 25.715 ;
     RECT  39.456 24.947 40.512 26.099 ;
     RECT  10.5 23.987 10.812 26.197 ;
     RECT  17.616 25.715 18.912 26.243 ;
     RECT  22.896 24.469 22.92 26.243 ;
     RECT  25.536 25.235 25.56 26.243 ;
     RECT  20.112 25.715 21.864 26.245 ;
     RECT  20.112 26.245 22.824 26.291 ;
     RECT  22.8 26.291 22.824 26.387 ;
     RECT  10.368 26.197 10.812 26.725 ;
     RECT  13.2 18.563 13.704 26.773 ;
     RECT  15.9 24.469 16.632 26.773 ;
     RECT  17.856 26.243 18.912 26.773 ;
     RECT  20.112 26.291 21.612 26.773 ;
     RECT  15.552 26.773 16.632 26.821 ;
     RECT  2.4 15.491 2.712 27.009 ;
     RECT  5.1 14.435 5.412 27.009 ;
     RECT  7.8 23.411 8.112 27.009 ;
     RECT  17.856 26.773 21.612 27.009 ;
     RECT  24 25.235 24.312 27.009 ;
     RECT  26.7 21.683 27.012 27.009 ;
     RECT  29.4 18.275 29.712 27.009 ;
     RECT  32.1 25.715 32.412 27.009 ;
     RECT  34.8 22.115 35.112 27.009 ;
     RECT  37.5 24.563 37.812 27.009 ;
     RECT  40.2 26.099 40.512 27.009 ;
     RECT  42.9 23.891 43.212 27.009 ;
     RECT  45.6 23.363 45.912 27.009 ;
     RECT  48.3 18.035 48.612 27.009 ;
     RECT  51 17.699 51.312 27.009 ;
     RECT  53.7 17.795 54.012 27.009 ;
     RECT  56.4 17.987 56.712 27.009 ;
     RECT  59.1 17.123 59.412 27.009 ;
     RECT  61.8 8.003 62.112 27.009 ;
     RECT  2.4 27.009 2.52 27.023 ;
     RECT  5.1 27.009 5.22 27.023 ;
     RECT  7.8 27.009 7.92 27.023 ;
     RECT  17.856 27.009 21.42 27.023 ;
     RECT  24 27.009 24.12 27.023 ;
     RECT  26.7 27.009 26.82 27.023 ;
     RECT  29.4 27.009 29.52 27.023 ;
     RECT  32.1 27.009 32.22 27.023 ;
     RECT  34.8 27.009 34.92 27.023 ;
     RECT  37.5 27.009 37.62 27.023 ;
     RECT  40.2 27.009 40.32 27.023 ;
     RECT  42.9 27.009 43.02 27.023 ;
     RECT  45.6 27.009 45.72 27.023 ;
     RECT  48.3 27.009 48.42 27.023 ;
     RECT  51 27.009 51.12 27.023 ;
     RECT  53.7 27.009 53.82 27.023 ;
     RECT  56.4 27.009 56.52 27.023 ;
     RECT  59.1 27.009 59.22 27.023 ;
     RECT  61.8 27.009 61.92 27.023 ;
     RECT  12.672 26.773 14.568 27.205 ;
     RECT  15.552 26.821 16.872 27.205 ;
     RECT  12.672 27.205 16.872 27.301 ;
     RECT  10.368 26.725 10.968 27.877 ;
     RECT  12.096 27.301 16.872 27.925 ;
     RECT  17.856 27.023 21.192 27.925 ;
     RECT  10.368 27.877 11.112 28.453 ;
     RECT  12.096 27.925 21.192 28.453 ;
     RECT  10.368 28.453 21.192 29.029 ;
     RECT  10.368 29.029 21.336 29.075 ;
     RECT  10.656 29.075 21.336 29.136 ;
  END
END qkd_seq_core_static
END LIBRARY
